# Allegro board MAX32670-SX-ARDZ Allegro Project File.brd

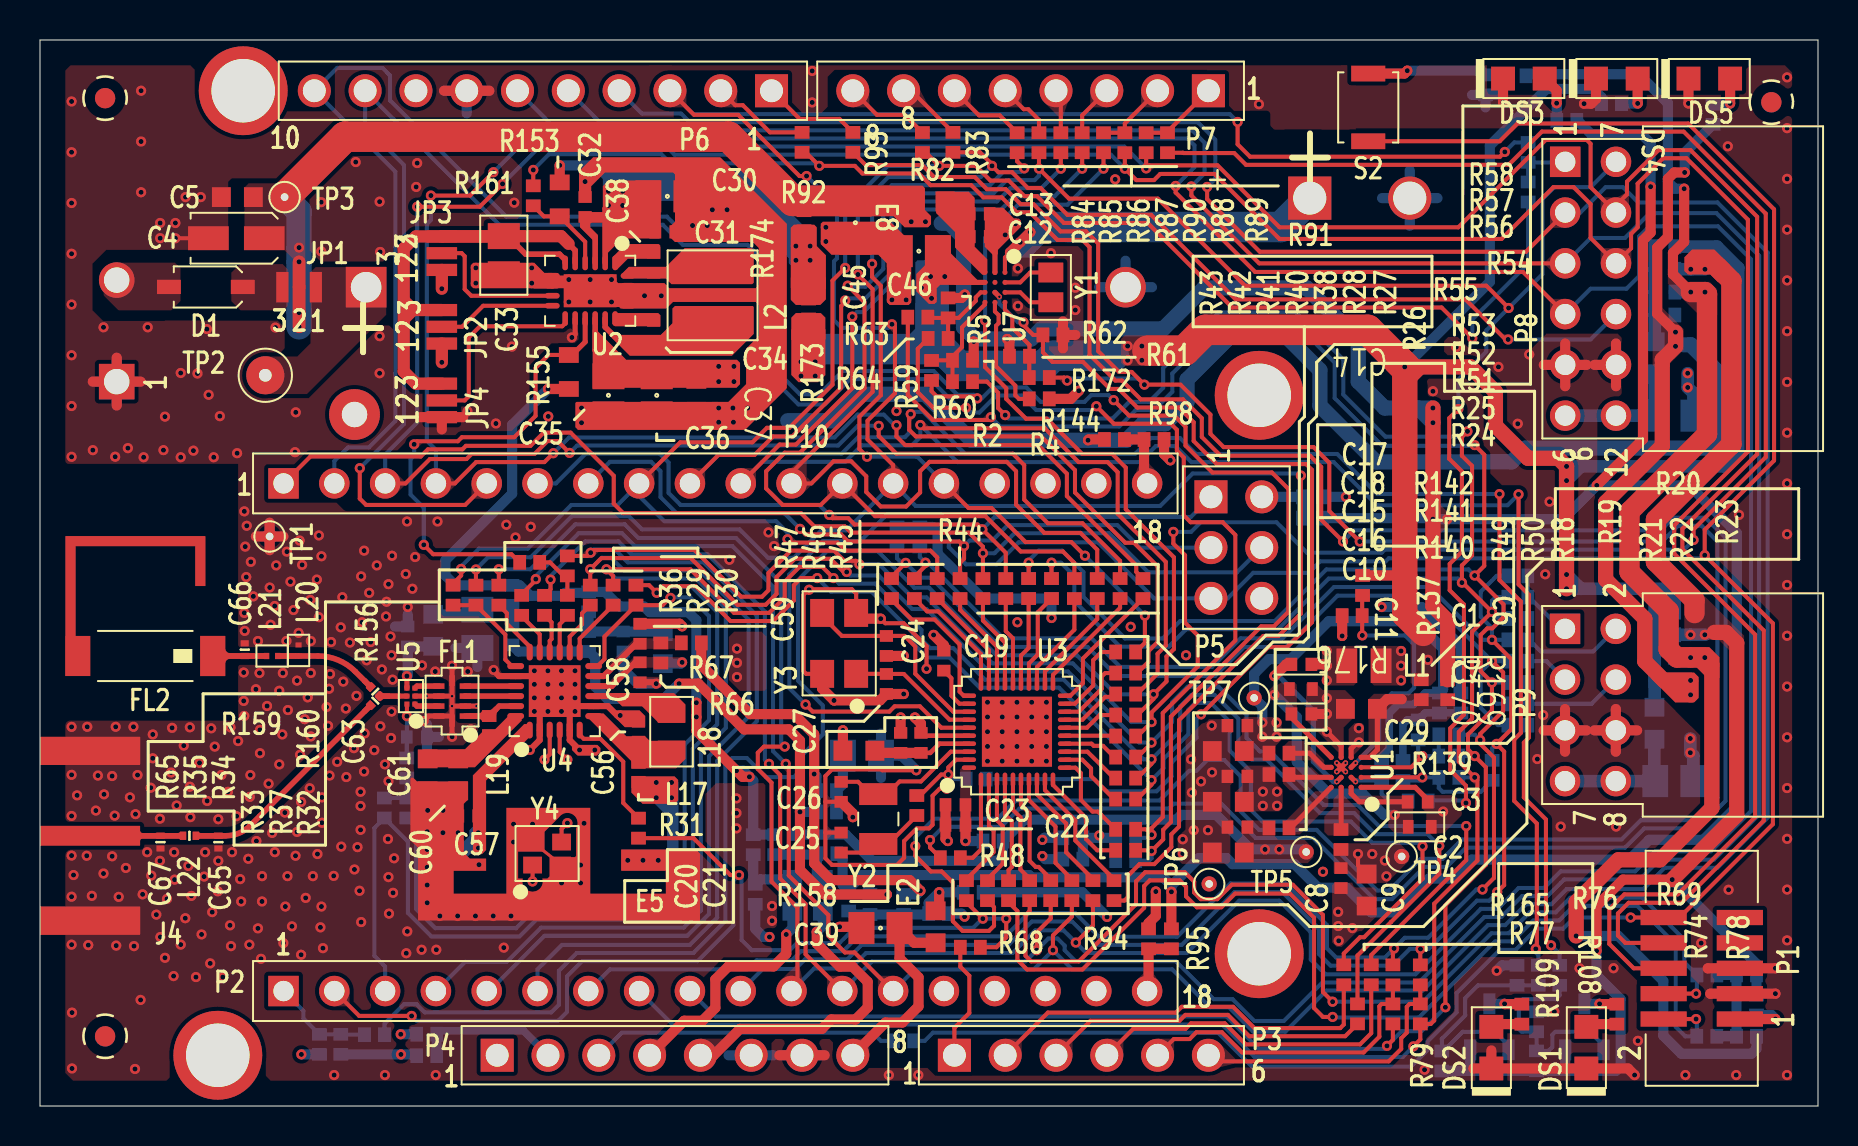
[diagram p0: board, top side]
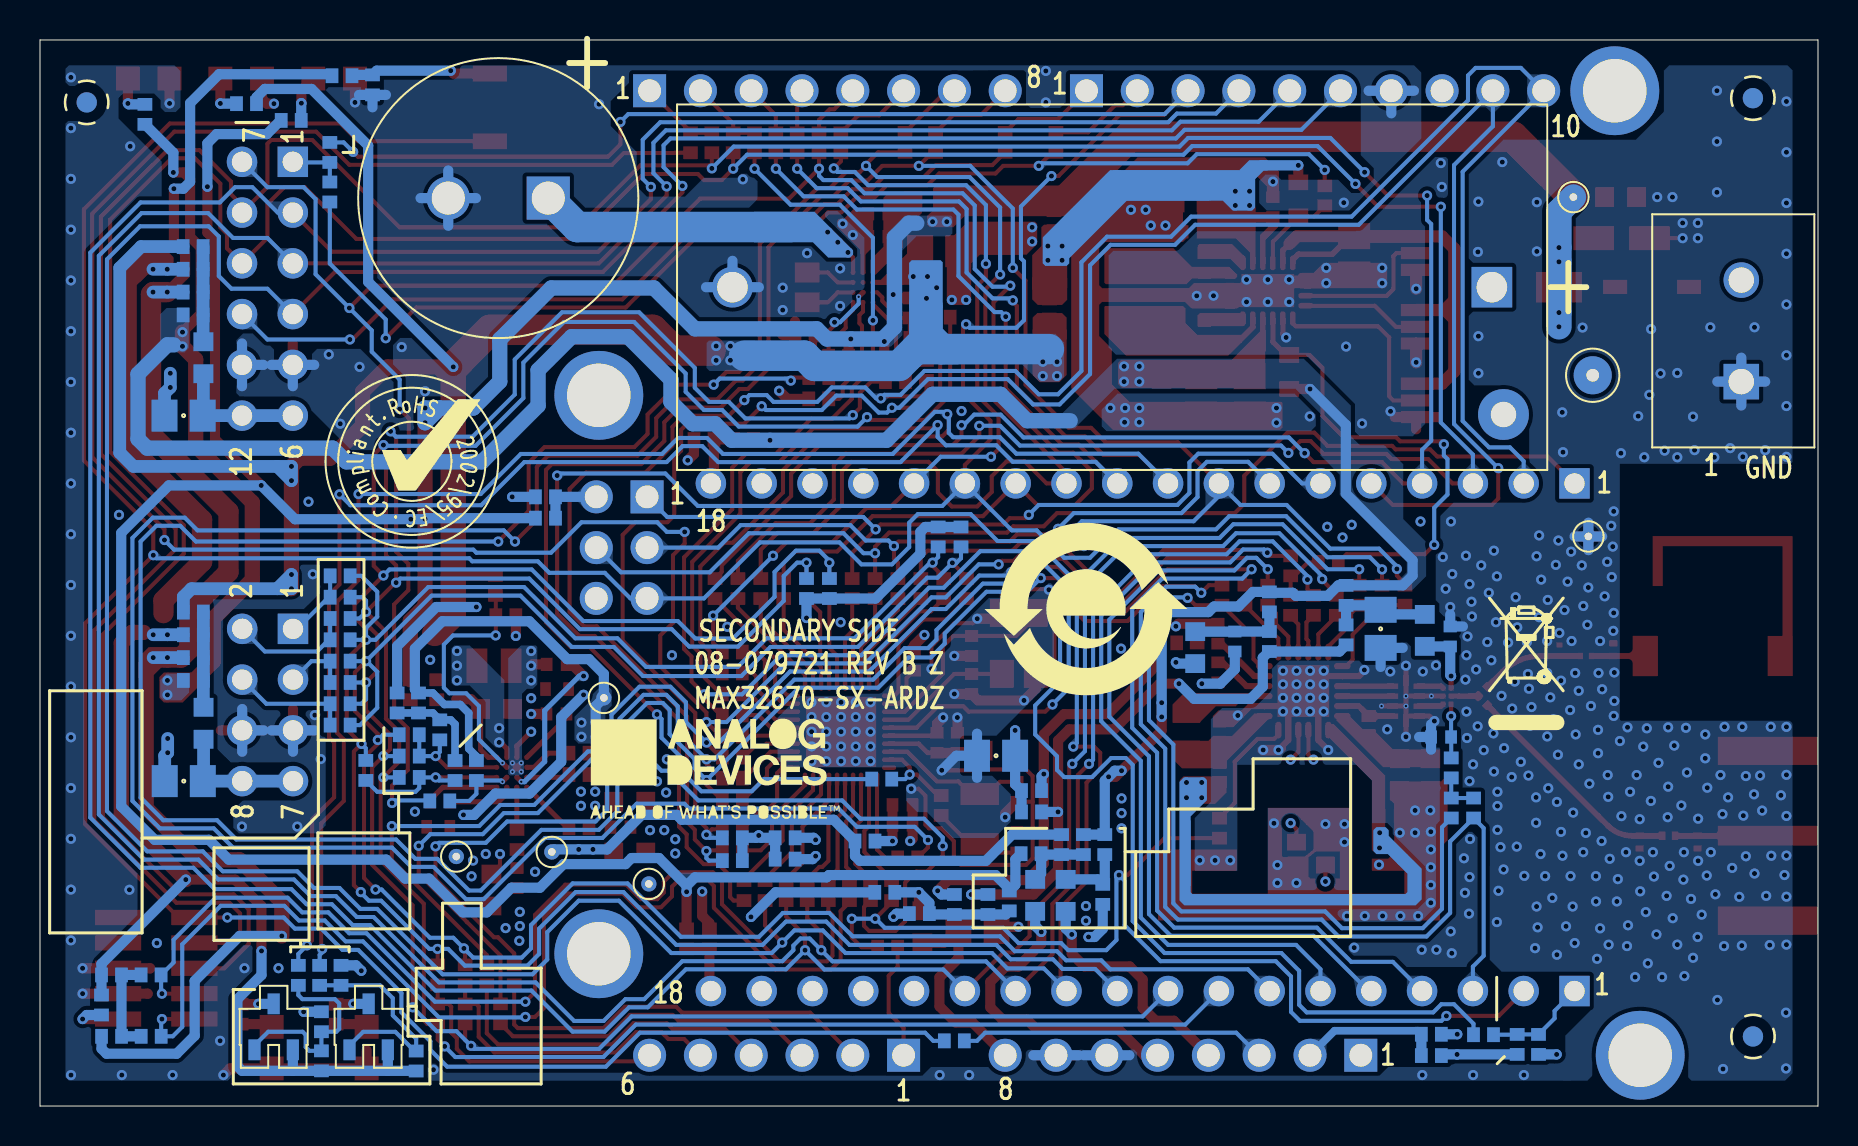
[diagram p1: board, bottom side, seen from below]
Outline 88.9 x 53.34 mm; copper layers: TOP, L2_GND, L3_PWR, BOTTOM. Coordinates in mm from the lower left corner of the outline.
Outline path: 0,53.34 88.9,53.34 88.9,0 0,0 0,53.34

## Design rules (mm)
constraint set DEFAULT: min track width 0.203
net group 50OHM-CPWG: nets RFI_N_1261 RFI_P_1261 RFO_1261 UNNAMED_9_CAP_I41_N1 UNNAMED_9_CAP_I108_N1 UNNAMED_9_CAP_I108_N2 UNNAMED_9_CAP_I126_N1 UNNAMED_9_FLTRBP10P_I89_SWRFI UNNAMED_9_FLTRBP10P_I89_SWRFO UNNAMED_9_IND_I127_N2

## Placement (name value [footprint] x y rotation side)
BT1  BH123A  [SKTMPDBH123A]  16.31 40.97 0 bottom
C1  0.01uF  [C0402]  63.07 22.1 180 top
C2  10UF  [C0402H32]  68.99 13.97 180 top
C3  0.01uF  [C0402]  68.88 15.21 180 top
C4  10uF  [C3216]  9.82 43.42 180 top
C5  1uF  [C0603]  9.87 45.48 0 top
C6  10UF  [C0402H32]  63.05 20.86 0 top
C7  0.01uF  [C0402]  63.07 19.62 0 top
C8  0.01uF  [C0402]  65.05 11.4 270 top
C9  22uF  [C0603]  66.33 10.81 270 top
C10  0.01uF  [C0402]  59.87 13.95 180 top
C11  47UF  [C0603]  59.41 12.68 180 top
C12  0.1uF  [C0402]  46.99 43.5 0 top
C13  1UF  [C0402]  46.99 44.64 0 top
C14  0.33F  [CPLTH197D531H327]  63.49 45.43 0 bottom
C15  0.01uF  [C0402]  59.87 16.49 180 top
C16  47UF  [C0603]  59.41 15.22 180 top
C17  0.01uF  [C0402]  59.87 19.03 180 top
C18  22uF  [C0603]  59.41 17.76 180 top
C19  4.7NF  [C0402]  45.19 22.28 90 top
C20  1UF  [C0402]  43.03 18.17 270 top
C21  0.1uF  [C0402]  44.05 18.17 270 top
C22  1UF  [C0402]  45.77 14.06 180 top
C23  0.1uF  [C0402]  45.77 15.07 180 top
C24  12pF  [C0402]  42.32 23.02 270 top
C25  0.1uF  [C0402]  40.06 13.18 90 top
C26  0.1uF  [C0402]  40.06 15.72 270 top
C27  12pF  [C0402]  42.32 21.12 270 top
C28  1NF  [C0402]  18.39 23.49 270 bottom
C29  22uF  [C0603]  66.07 19.87 0 top
C30  10uF  [C0805H60]  31.37 45.52 180 top
C31  1UF  [C0402]  31.27 43.74 180 top
C32  1UF  [C0402]  27.25 44.98 270 top
C33  4.7uF  [C0805H53]  23.19 42.57 90 top
C34  0.1uF  [C0402]  30.68 38.79 270 top
C35  22UF  [C0805H60]  28.42 35.56 270 top
C36  22UF  [C0805H60]  30.84 35.56 270 top
C37  0.1uF  [C0603]  32.82 35.56 270 top
C38  0.1uF  [C0402]  30.68 42.19 270 top
C39  22UF  [C0805H60]  42.02 8.9 180 top
C40  22UF  [C0805H60]  81.72 34.54 0 bottom
C41  22UF  [C0805H60]  81.71 16.26 0 bottom
C42  22UF  [C0805H60]  41.1 17.53 0 bottom
C43  22UF  [C0402]  29.16 23.24 90 bottom
C44  22UF  [C0805H60]  21.87 23.88 270 bottom
C45  22UF  [C0805H60]  40.77 44.2 270 top
C46  22UF  [C0805H60]  43.94 42.77 180 top
C56  0.47UF  [C0402]  29.93 18.73 90 top
C57  10NF  [C0402]  21.42 14.51 0 top
C58  100NF  [C0402]  30 21.7 90 top
C59  100NF  [C0402]  30 23.63 90 top
C60  47NF  [C0603]  20.91 16.57 270 top
C61  47pF  [C0603]  19.38 16.57 270 top
C62  1NF  [C0402]  18.85 18.47 0 bottom
C63  39pF  [C0201]  16.77 20.29 45 top
C65  3.3pF  [C0201]  8.92 13.2 270 top
C66  2.4pF  [C0201]  10.24 22.83 90 top
C67  3.3pF  [C0201]  6.02 13.2 270 top
D1  1N5819HW-7-F  [SOD123-3]  8.29 40.98 180 top
DS1  SML-LXT0805YW-TR  [LXT0805]  77.32 2.92 90 top
DS2  SML-LXT0805YW-TR  [LXT0805]  72.57 2.92 90 top
DS3  SML-LXT0805YW-TR  [LXT0805]  74.19 51.41 0 top
DS4  SML-LXT0805YW-TR  [LXT0805]  78.84 51.41 0 top
DS5  SML-LXT0805YW-TR  [LXT0805]  83.46 51.41 0 top
E1  120OHM AT 100MEGHZ  [L0603]  37.62 10.54 90 bottom
E2  120OHM AT 100MEGHZ  [L0603]  44.78 8.97 90 top
E3  120OHM AT 100MEGHZ  [L0603]  80.72 19.15 90 bottom
E4  120OHM AT 100MEGHZ  [L0603]  80.73 37.44 90 bottom
E5  120OHM AT 100MEGHZ  [L0603]  40.94 17.78 0 top
E6  120OHM AT 100MEGHZ  [L0603]  31.14 22.94 270 bottom
E7  120OHM AT 100MEGHZ  [L0603]  19.66 23.8 270 bottom
E8  120OHM AT 100MEGHZ  [L0603]  44.45 45.26 0 top
E9  120OHM AT 100MEGHZ  [L0603]  39.14 10.54 90 bottom
FL1  862-928MEGHZ  [FLSML79W49H35]  20.6 20.26 90 top
FL2  915MEGHz  [FLSML276W79H35]  5.26 22.52 180 top
J4  32K145-400L5  [CNSMAL559W374H169]  2.36 13.52 180 top
JP1  3PIN_SOLDER_JUMPER  [JPRSLD03]  12.95 40.97 180 top
JP2  3PIN_SOLDER_JUMPER  [JPRSLD03]  20.09 38.99 90 top
JP3  3PIN_SOLDER_JUMPER  [JPRSLD03]  20.09 42.67 90 top
JP4  3PIN_SOLDER_JUMPER  [JPRSLD03]  20.09 35.31 90 top
L1  1.5UH  [L0806-2]  66.2 22.03 0 top
L2  10uH  [LSMSQ157H161]  33.63 40.56 90 top
L17  47nH  [L0402]  29.93 16.7 270 top
L18  15UH  [L0805H57]  31.58 18.73 90 top
L19  47nH  [L0402]  22.46 19.03 90 top
L20  12NH  [L0201H13]  12.93 22.79 270 top
L21  1NH  [L0201H13]  11.61 22.52 180 top
L22  0  [R0201]  7.47 13.52 180 top
NOREF  -  [unnamed]  3.26 50.43 0 top
NOREF#2  -  [#2]  44.88 75.51 0 top
NOREF#3  -  [#2]  -26.27 -60.11 0 top
NOREF#4  -  [unnamed]  10.16 50.8 0 top
NOREF#5  -  [#2]  -31.35 -65.19 0 top
NOREF#6  -  [#2]  -26.27 -60.11 0 top
NOREF#7  -  [#2]  -31.35 -65.19 0 top
NOREF#8  -  [#2]  88.9 0 90 top
NOREF#9  -  [#2]  134.79 111.23 0 top
NOREF#10  -  [#2]  -31.35 -65.19 0 top
NOREF#11  -  [unnamed]  8.89 2.54 90 top
NOREF#12  -  [unnamed]  60.96 35.56 270 top
NOREF#13  -  [unnamed]  60.96 7.62 180 top
NOREF#14  -  [#2]  210.96 263.61 0 top
NOREF#15  -  [#2]  -26.27 -60.11 0 top
NOREF#16  -  [unnamed]  86.57 50.22 0 top
NOREF#17  -  [#2]  0 53.34 0 top
NOREF#18  -  [unnamed]  3.26 3.49 0 top
NOREF#19  -  [unnamed]  3.26 50.43 180 bottom
NOREF#20  -  [unnamed]  86.56 50.22 180 bottom
NOREF#21  -  [#2]  70.31 32.26 180 bottom
NOREF#22  -  [#2]  14.78 18.87 180 bottom
NOREF#23  -  [#2]  55.45 16.84 180 bottom
NOREF#24  -  [#2]  36.6 24.87 180 bottom
NOREF#25  -  [unnamed]  3.25 3.48 180 bottom
P1  3220-10-0300-00  [CNSMMHDR2X5L443W201H228]  83.09 6.89 90 top
P2  FPH25448-S18S1014272640B  [CNTHMHDR1X18L1800W98H421]  12.18 5.75 0 top
P3  SSQ-106-03-G-S  [CNSAMTECSSQ-106-XX-X-S]  45.72 2.54 0 top
P4  SSQ-108-03-G-S  [CNSAMTECSSQ-108-XX-X-S]  22.86 2.54 0 top
P5  67996-406HLF  [CNTHMHDR2X3L300W190H338]  58.55 30.48 270 top
P6  SSQ-110-03-G-S  [CNSAMTECSSQ-110-XX-X-S]  36.58 50.8 180 top
P7  SSQ-108-03-G-S  [CNSAMTECSSQ-108-XX-X-S]  58.42 50.8 180 top
P8  PPPC062LJBN-RC  [CNHDRRA2X6H205]  76.26 47.24 270 top
P9  PPPC042LJBN-RC  [CNHDRRA2X4H206]  76.25 23.88 270 top
P10  FPH25448-S18S1014272640B  [CNTHMHDR1X18L1800W98H421]  12.18 31.15 0 top
P11  OSTTC022162  [CNHDR1X2H406]  3.84 36.25 90 bottom
Q1  PMV65XP,215  [SOT23_B]  77.22 3.96 180 bottom
Q2  PMV65XP,215  [SOT23_B]  72.47 3.96 180 bottom
R1  10K  [R0402]  54.28 12.28 0 bottom
R2  10K  [R0402]  46.13 37.31 180 top
R3  10K  [R0402]  54.28 13.42 0 bottom
R4  0  [R0402]  49.96 35.38 180 top
R5  10K  [R0402]  45.41 39.93 270 top
R6  0  [R0402]  51.64 12.35 0 bottom
R7  0  [R0402]  51.64 13.42 0 bottom
R8  10K  [R0402]  50.58 25.89 90 bottom
R9  10K  [R0402]  49.43 25.89 90 bottom
R10  0  [R0402]  63.63 30.48 180 bottom
R11  0  [R0402]  63.63 29.41 180 bottom
R12  0  [R0402]  41.5 10.08 90 bottom
R13  0  [R0402]  43.18 10.08 90 bottom
R14  10K  [R0402]  83.34 3.49 180 bottom
R15  10K  [R0402]  83.35 6.56 180 bottom
R16  10K  [R0402]  73.8 51.55 180 bottom
R17  0  [R0402]  72.28 51.09 270 bottom
R18  0  [R0402]  48.43 10.78 270 top
R19  0  [R0402]  49.48 10.78 270 top
R20  0  [R0402]  50.54 10.78 270 top
R21  0  [R0402]  51.59 10.78 270 top
R22  0  [R0402]  52.65 10.78 270 top
R23  0  [R0402]  53.7 10.78 270 top
R24  0  [R0402]  54.28 12.8 0 top
R25  0  [R0402]  54.28 13.85 0 top
R26  0  [R0402]  55.15 25.89 90 top
R27  0  [R0402]  54 25.89 90 top
R28  0  [R0402]  52.86 25.89 90 top
R29  0  [R0402]  28.66 25.56 270 top
R30  0  [R0402]  29.8 25.56 270 top
R31  0  [R0402]  29.93 13.9 90 top
R32  0  [R0402]  26.37 25.05 270 top
R33  0  [R0402]  24.08 25.05 270 top
R34  0  [R0402]  22.94 25.56 270 top
R35  0  [R0402]  21.8 25.56 270 top
R36  0  [R0402]  27.51 25.56 90 top
R37  0  [R0402]  25.23 25.05 90 top
R38  0  [R0402]  51.72 25.89 90 top
R39  100  [R0402]  18.34 16.92 90 bottom
R40  0  [R0402]  50.58 25.89 90 top
R41  0  [R0402]  49.43 25.89 90 top
R42  0  [R0402]  48.29 25.89 90 top
R43  0  [R0402]  47.15 25.89 90 top
R44  0  [R0402]  46 25.89 90 top
R45  0  [R0402]  44.86 25.89 90 top
R46  0  [R0402]  43.72 25.89 90 top
R47  0  [R0402]  42.57 25.89 90 top
R48  0  [R0402]  45.52 12.42 180 top
R49  0  [R0402]  46.32 10.78 270 top
R50  0  [R0402]  47.38 10.78 270 top
R51  0  [R0402]  54.28 15.36 0 top
R52  0  [R0402]  54.28 16.41 0 top
R53  0  [R0402]  54.28 17.46 0 top
R54  0  [R0402]  54.28 18.51 0 top
R55  0  [R0402]  54.28 19.56 0 top
R56  0  [R0402]  54.28 20.61 0 top
R57  0  [R0402]  54.28 21.67 0 top
R58  0  [R0402]  54.28 22.72 0 top
R59  0  [R0402]  44.58 36.8 90 top
R60  0  [R0402]  46.13 36.25 180 top
R61  10K  [R0402]  48.97 37.52 0 top
R62  0  [R0402]  50.65 38.58 0 top
R63  0  [R0402]  43.89 39.47 180 top
R64  0  [R0402]  44.91 38.4 180 top
R65  0  [R0402]  20.65 25.56 270 top
R66  0  [R0402]  31.04 22.67 90 top
R67  0  [R0402]  32.57 23.17 180 top
R68  0  [R0402]  46.52 7.95 0 top
R69  0  [R0402]  65.19 6.57 90 top
R70  0  [R0402]  81.24 41.87 0 bottom
R71  0  [R0402]  81.24 40.73 0 bottom
R72  0  [R0402]  81.23 23.58 0 bottom
R73  0  [R0402]  81.23 22.44 0 bottom
R74  0  [R0402]  65.87 4.61 90 top
R75  0  [R0402]  43.18 3.26 0 bottom
R76  0  [R0402]  69.02 6.56 90 top
R77  0  [R0402]  67.64 6.56 90 top
R78  0  [R0402]  67.64 4.61 270 top
R79  0  [R0402]  69.02 4.61 270 top
R80  0  [R0402]  19.33 2.52 180 bottom
R81  0  [R0402]  19.33 3.59 180 bottom
R82  0  [R0402]  44.12 48.21 90 top
R83  0  [R0402]  45.65 48.22 90 top
R84  0  [R0402]  48.86 48.2 90 top
R85  0  [R0402]  49.95 48.2 90 top
R86  0  [R0402]  51.04 48.2 90 top
R87  0  [R0402]  52.11 48.2 90 top
R88  0  [R0402]  54.24 48.2 90 top
R89  0  [R0402]  55.31 48.2 90 top
R90  0  [R0402]  53.17 48.2 90 top
R91  0  [R0402]  56.38 48.2 90 top
R92  0  [R0402]  38.1 48.22 90 top
R93  0  [R0402]  40.64 48.22 90 top
R94  0  [R0402]  55.43 8.37 90 top
R95  0  [R0402]  56.57 8.37 90 top
R96  0  [R0402]  74.41 45.73 90 bottom
R97  0  [R0402]  74.41 47.71 270 bottom
R98  0  [R0402]  55.7 33.35 0 top
R99  0  [R0402]  39.32 15.78 0 bottom
R100  0  [R0402]  39.32 14.72 0 bottom
R101  0  [R0402]  47.65 13.26 0 bottom
R102  0  [R0402]  75.98 6.54 270 bottom
R103  0  [R0402]  74.92 6.54 270 bottom
R104  1.1K  [R0402]  74.83 2.26 90 bottom
R105  150K  [R0402]  74.83 4.22 90 bottom
R106  1.1K  [R0402]  70.09 2.25 90 bottom
R107  150K  [R0402]  73.85 6.54 90 bottom
R108  470  [R0402]  78.84 4.6 270 top
R109  470  [R0402]  74.09 4.6 270 top
R110  0  [R0402]  73.89 26.53 0 bottom
R111  0  [R0402]  73.89 25.46 0 bottom
R112  0  [R0402]  73.89 21.19 0 bottom
R113  0  [R0402]  73.89 22.26 0 bottom
R114  0  [R0402]  73.89 23.33 180 bottom
R115  0  [R0402]  73.89 24.39 180 bottom
R116  0  [R0402]  73.89 20.13 180 bottom
R117  0  [R0402]  73.89 19.06 180 bottom
R118  10K  [R0402]  43.99 28.47 270 bottom
R119  10K  [R0402]  42.85 28.47 270 bottom
R120  10K  [R0402]  67.08 16.79 90 bottom
R121  4.7K  [R0402]  68.91 18.82 270 bottom
R122  4.7K  [R0402]  68.15 16.79 270 bottom
R123  0  [R0402]  70.44 18.58 0 bottom
R124  0  [R0402]  70.44 17.51 0 bottom
R125  0  [R0402]  70.44 16.44 0 bottom
R126  0  [R0402]  72.61 16.79 90 bottom
R127  0  [R0402]  44.93 9.63 0 bottom
R128  0  [R0402]  85.32 3.49 180 bottom
R129  0  [R0402]  85.33 6.56 180 bottom
R130  10K  [R0402]  13.97 3.08 90 bottom
R131  10K  [R0402]  15.04 3.08 90 bottom
R132  0  [R0402]  16.73 3.57 180 bottom
R133  0  [R0402]  81.24 39.58 0 bottom
R134  0  [R0402]  81.23 21.29 0 bottom
R135  0  [R0402]  17.22 14.91 90 bottom
R136  0  [R0402]  18.34 14.91 90 bottom
R137  0  [R0402]  66.13 26.05 270 top
R138  0  [R0402]  40.44 10.26 90 bottom
R139  0  [R0402]  65.05 13.34 270 top
R140  0  [R0402]  61.95 13.92 180 top
R141  0  [R0402]  61.95 16.59 180 top
R142  0  [R0402]  61.95 17.65 180 top
R143  0  [R0402]  35.66 13.08 90 bottom
R144  0  [R0402]  53.72 33.35 180 top
R145  0  [R0402]  27.43 25.22 270 bottom
R146  0  [R0402]  27.43 23.24 90 bottom
R147  0  [R0402]  23.6 25.55 270 bottom
R148  0  [R0402]  23.6 23.57 90 bottom
R149  0  [R0402]  71.04 20.17 270 bottom
R150  0  [R0402]  69.98 20.17 270 bottom
R151  470  [R0402]  76.34 49.31 180 bottom
R152  470  [R0402]  78.57 50.15 0 bottom
R153  2MEG  [R0603]  25.98 45.36 270 top
R154  470  [R0402]  83.65 49.62 90 bottom
R155  2MEG  [R0603]  26.44 36.73 270 top
R156  0  [R0201]  16.77 20.74 135 top
R157  0  [R0402]  46.81 16.36 0 bottom
R158  0  [R0402]  43.84 15.04 270 top
R159  0  [R0402]  24.49 27.2 0 top
R160  0  [R0402]  26.37 27.03 270 top
R161  0  [R0402]  24.66 45.54 270 top
R162  0  [R0402]  39.34 12.62 0 bottom
R163  0  [R0402]  37.82 13.08 90 bottom
R164  0  [R0402]  36.73 13.08 90 bottom
R165  0  [R0402]  66.56 6.57 90 top
R166  0  [R0402]  46.66 10.69 0 bottom
R167  0  [R0402]  81.23 24.71 0 bottom
R168  0  [R0402]  81.24 43 0 bottom
R169  0  [R0402]  70.38 20.83 270 top
R170  0  [R0402]  69.06 20.83 270 top
R171  0  [R0402]  68.91 15.27 0 bottom
R172  0  [R0402]  49.96 36.45 0 top
R173  0  [R0402]  38.43 39.88 90 top
R174  0  [R0402]  38.2 44.3 270 top
R175  0  [R0402]  85.83 5.05 270 bottom
R176  0  [R0402]  65.61 24.54 180 top
R177  0  [R0402]  35.76 10.59 270 bottom
S1  B3U-1000P  [SWSML118W98H69]  66.41 49.97 270 top
TP1  TESTPAD  [TPC30D15]  11.48 28.5 0 top
TP2  TESTPAD  [TPC75D25]  11.26 36.56 0 top
TP3  TESTPAD  [TPC30D15]  12.23 45.48 0 top
TP4  TESTPAD  [TPC30D15]  68.08 12.48 0 top
TP5  TESTPAD  [TPC30D15]  63.31 12.71 0 top
TP6  TESTPAD  [TPC30D15]  58.46 11.11 0 top
TP7  TESTPAD  [TPC30D15]  60.71 20.42 0 top
U1  MAX77675AEWE+  [WLCSP16H27_A]  65.31 16.7 90 top
U2  LTC3130EUDC-1#PBF  [QFN20_4X3_PAD2_65X1_65]  27.51 40.79 180 top
U3  MAX32670GTL+  [QFN40_5X5_PAD3_5X3_5]  48.85 18.73 0 top
U4  SX1261IMLTRT  [QFN24_4X4_PAD2_6X2_6]  25.73 20.76 0 top
U5  BGS12WN6E6327XTSA1  [TSNP-6-10]  18.55 20.51 90 top
U7  MAX31334EWC+  [WLP12_1_968X1_468H0_69]  47.75 40.96 270 top
Y1  32.768KHZ  [YSML81W47H24_A]  50.54 40.96 270 top
Y2  32.768KHZ  [YSML126W59H35]  41.91 14.36 90 top
Y3  32MHZ  [YSML160W98H32]  39.96 23.15 90 top
Y4  32MEGHZ  [YSML79W63H20]  25.35 12.63 0 top

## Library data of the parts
BT1 = SKTBAT2P: User Part Number: UPN; Tolerance: N/A; alternate symbols: (SKTMPDBH123A); part number: SKTBAT2P_TH-BH123A,E062744,SKTMPDBH123A; tolerance: N/A
C1 C3 C7 C8 C10 C15 C17 = CAP: User Part Number: UPN; Tolerance: 10; alternate symbols: (C0402); part number: CAP_SM-0.01UF,25V,10,E013688,C0402; tolerance: 10
C2 C6 = CAP: User Part Number: UPN; Tolerance: 20; alternate symbols: (C0402H32); part number: CAP_SM-10UF,10V,20,E057793,C0402H32; tolerance: 20
C4 = CAPP: Tolerance: 20; User Part Number: UPN; alternate symbols: (C3216); part number: CAPP_SM-10UF,20V,20,E018828,C3216; tolerance: 20
C5 = CAP: User Part Number: UPN; Tolerance: 10; alternate symbols: (C0603); part number: CAP_SM-1UF,16V,10,E020111,C0603; tolerance: 10
C9 C18 = CAP: User Part Number: UPN; Tolerance: 20; alternate symbols: (C0603); part number: CAP_SM-22UF,10V,20,E022680,C0603; tolerance: 20
C11 C16 = CAP: User Part Number: UPN; Tolerance: 20; alternate symbols: (C0603); part number: CAP_SM-47UF,6.3V,20,E061424,C0603; tolerance: 20
C12 C21 C23 C25 C26 C34 C38 = CAP: User Part Number: UPN; Tolerance: 10; alternate symbols: (C0402); part number: CAP_SM-0.1UF,50V,10,E025746,C0402; tolerance: 10
C13 C20 C22 C31 C32 = CAP: User Part Number: UPN; Tolerance: 10; alternate symbols: (C0402); part number: CAP_SM-1UF,25V,10,E054542,C0402; tolerance: 10
C14 = CAPP: User Part Number: UPN; Tolerance: -20%,+80; alternate symbols: (CPLTH197D531H327); part number: CAPP_TH-0.33F,5.5V,-20%,+80,E062377,CPLTH197D531H327; tolerance: -20%,+80
C19 = CAP: User Part Number: UPN; Tolerance: 10; alternate symbols: (C0402); part number: CAP_SM-4.7NF,16V,10,E042800,C0402; tolerance: 10
C24 C27 = CAP: User Part Number: UPN; Tolerance: 5; alternate symbols: (C0402); part number: CAP_SM-12PF,50V,5,E033360,C0402; tolerance: 5
C28 C62 = CAP: User Part Number: UPN; Tolerance: 10; alternate symbols: (C0402); part number: CAP_SM-1NF,25V,10,E042764,C0402; tolerance: 10
C29 = CAP: User Part Number: UPN; Tolerance: 20; alternate symbols: (C0603); part number: CAP_SM-22UF,10V,20,E035951,C0603; tolerance: 20
C30 = CAP: Tolerance: 10; User Part Number: UPN; alternate symbols: (C0805H60); part number: CAP_SM-10UF,25V,10,E026259,C0805H60; tolerance: 10
C33 = CAP: Tolerance: 10; User Part Number: UPN; alternate symbols: (C0805H53); part number: CAP_SM-4.7UF,50V,10,E028468,C0805H53; tolerance: 10
C35 C36 C39-C42 C44-C46 = CAP: Tolerance: 20; User Part Number: UPN; alternate symbols: (C0805H60); part number: CAP_SM-22UF,10V,20,E059803,C0805H60; tolerance: 20
C37 = CAP: User Part Number: UPN; Tolerance: 10; alternate symbols: (C0603); part number: CAP_SM-0.1UF,25V,10,E007204,C0603; tolerance: 10
C43 = CAP: User Part Number: UPN; Tolerance: 20; alternate symbols: (C0402); part number: CAP_SM-22UF,6.3V,20,E059974,C0402; tolerance: 20
C56 = CAP: User Part Number: UPN; Tolerance: 10; alternate symbols: (C0402); part number: CAP_SM-0.47UF,16V,10,E047983,C0402; tolerance: 10
C57 = CAP: User Part Number: UPN; Tolerance: 10; alternate symbols: (C0402); part number: CAP_SM-10NF,25V,10,E046235,C0402; tolerance: 10
C58 C59 = CAP: User Part Number: UPN; Tolerance: 10; alternate symbols: (C0402); part number: CAP_SM-100NF,25V,10,E060176,C0402; tolerance: 10
C60 = CAP: User Part Number: UPN; Tolerance: 10; alternate symbols: (C0603); part number: CAP_SM-47NF,100V,10,E044215,C0603; tolerance: 10
C61 = CAP: User Part Number: UPN; Tolerance: 5; alternate symbols: (C0603); part number: CAP_SM-47PF,100V,5,E007959,C0603; tolerance: 5
C63 = CAP: Tolerance: 5; User Part Number: UPN; alternate symbols: (C0201); part number: CAP_SM-39PF,25V,5,E026816,C0201; tolerance: 5
C65 C67 = CAP: Tolerance: 0.25pF; User Part Number: UPN; alternate symbols: (C0201); part number: CAP_SM-3.3PF,25V,0.25PF,E017482,C0201; tolerance: 0.25pF
C66 = CAP: Tolerance: 0.1pF; User Part Number: UPN; alternate symbols: (C0201); part number: CAP_SM-2.4PF,25V,0.1PF,E031690,C0201; tolerance: 0.1pF
D1 = DIOSCHOTTKY: Tolerance: N/A; User Part Number: UPN; alternate symbols: (SOD123-3); part number: DIOSCHOTTKY_SM-1N5819HW-7-F,40V,N/A,E014276,SOD123-3; tolerance: N/A
DS1-DS5 = DIOLED: Tolerance: N/A; User Part Number: UPN; alternate symbols: (LXT0805); part number: DIOLED_SM-SML-LXT0805YW-TR,N/A,N/A,E005351,LXT0805; tolerance: N/A
E1-E9 = FERRITE: User Part Number: UPN; Tolerance: 25; alternate symbols: (L0603); part number: FERRITE_SM-120OHM AT 100MEGHZ,25,E025768,L0603; tolerance: 25
FL1 = FLTRBP10P: User Part Number: UPN; Tolerance: N/A; alternate symbols: (FLSML79W49H35); part number: FLTRBP10P_SM-862-928MEGHZ,E062117,FLSML79W49H35; tolerance: N/A
FL2 = FLTRRF2P: Tolerance: N/A; User Part Number: UPN; alternate symbols: (FLSML276W79H35); part number: FLTRRF2P_SM-915MEGHZ,E014743,FLSML276W79H35; tolerance: N/A
J4 = CNBNC5P: Tolerance: N/A; User Part Number: UPN; alternate symbols: (CNSMAL559W374H169); part number: CNBNC5P_SM-32K145-400L5,E015227,CNSMAL559W374H169; tolerance: N/A
JP1-JP4 = NC3P_JMPR: Tolerance: N/A; User Part Number: UPN; alternate symbols: (JPRSLD03); part number: NC3P_JMPR_SM-3PIN_SOLDER_JUMPER,E005606,JPRSLD03; tolerance: N/A
L1 = IND: Tolerance: 20; User Part Number: UPN; alternate symbols: (L0806-2); part number: IND_SM-1.5UH,20,E062341,L0806-2; tolerance: 20
L2 = IND: User Part Number: UPN; Tolerance: 20; alternate symbols: (LSMSQ157H161); part number: IND_SM-10UH,20,E016513,LSMSQ157H161; tolerance: 20
L17 L19 = IND: User Part Number: UPN; Tolerance: 5; alternate symbols: (L0402); part number: IND_SM-47NH,5,E010282,L0402; tolerance: 5
L18 = IND: User Part Number: UPN; Tolerance: 20; alternate symbols: (L0805H57); part number: IND_SM-15UH,20,E062262,L0805H57; tolerance: 20
L20 = IND: Tolerance: 3; User Part Number: UPN; alternate symbols: (L0201H13); part number: IND_SM-12NH,3,E031685,L0201H13; tolerance: 3
L21 = IND: Tolerance: 0.1NH; User Part Number: UPN; alternate symbols: (L0201H13); part number: IND_SM-1NH,0.1NH,E025902,L0201H13; tolerance: 0.1NH
L22 R156 = RES: Tolerance: JUMPER; User Part Number: UPN; alternate symbols: (R0201); part number: RES_SM-0,E004015,1/20W,JUMPER,R0201; tolerance: JUMPER
P1 = CN10P: User Part Number: UPN; Tolerance: N/A; alternate symbols: (CNSMMHDR2X5L443W201H228); part number: CN10P_SM-3220-10-0300-00,E027502,CNSMMHDR2X5L443W201H228; tolerance: N/A
P2 P10 = CN18P: Tolerance: N/A; User Part Number: UPN; alternate symbols: (CNTHMHDR1X18L1800W98H421); part number: CN18P_TH-FPH25448-S18S1014272640B,E056935,CNTHMHDR1X18L1800W98H421; tolerance: N/A
P3 = CN6P: User Part Number: UPN; Tolerance: N/A; alternate symbols: (CNSAMTECSSQ-106-XX-X-S); part number: CN6P_TH-SSQ-106-03-G-S,E020477,CNSAMTECSSQ-106-XX-X-S; tolerance: N/A
P4 P7 = CN8P_A: User Part Number: UPN; Tolerance: N/A; alternate symbols: (CNSAMTECSSQ-108-XX-X-S); part number: CN8P_A_TH-SSQ-108-03-G-S,E020478,CNSAMTECSSQ-108-XX-X-S; tolerance: N/A
P5 = CN6P: User Part Number: UPN; Tolerance: N/A; alternate symbols: (CNTHMHDR2X3L300W190H338); part number: CN6P_TH-67996-406HLF,E027385,CNTHMHDR2X3L300W190H338; tolerance: N/A
P6 = CN10P: User Part Number: UPN; Tolerance: N/A; alternate symbols: (CNSAMTECSSQ-110-XX-X-S); part number: CN10P_TH-SSQ-110-03-G-S,E020479,CNSAMTECSSQ-110-XX-X-S; tolerance: N/A
P8 = CN12P_V3: User Part Number: UPN; Tolerance: N/A; alternate symbols: (CNHDRRA2X6H205); part number: CN12P_V3_TH-PPPC062LJBN-RC,E022332,CNHDRRA2X6H205; tolerance: N/A
P9 = CN8P_ODD_EVEN: User Part Number: UPN; Tolerance: N/A; alternate symbols: (CNHDRRA2X4H206); part number: CN8P_ODD_EVEN_TH-PPPC042LJBN-RC,E023816,CNHDRRA2X4H206; tolerance: N/A
P11 = CN2P: User Part Number: UPN; Tolerance: N/A; alternate symbols: (CNHDR1X2H406); part number: CN2P_TH-OSTTC022162,E016936,CNHDR1X2H406; tolerance: N/A
Q1 Q2 = TRANPMOSFET_V12: User Part Number: UPN; Tolerance: N/A; alternate symbols: (SOT23_B); part number: TRANPMOSFET_V12_SM-PMV65XP,215,E027303,SOT23_B; tolerance: N/A
R1-R3 R5 R8 R9 R14-R16 R61 R118-R120 R130 R131 = RES: User Part Number: UPN; Tolerance: 1; alternate symbols: (R0402); part number: RES_SM-10K,E003751,1/10W,1,R0402; tolerance: 1
R4 R6 R7 R10-R13 R17-R38 R40-R60 R62-R103 R110-R117 R123-R129 R132-R150 R157-R177 = RES: User Part Number: UPN; Tolerance: JUMPER; alternate symbols: (R0402); part number: RES_SM-0,E003438,1/10W,JUMPER,R0402; tolerance: JUMPER
R39 = RES: User Part Number: UPN; Tolerance: 5; alternate symbols: (R0402); part number: RES_SM-100,E003443,1/10W,5,R0402; tolerance: 5
R104 R106 = RES: User Part Number: UPN; Tolerance: 1; alternate symbols: (R0402); part number: RES_SM-1.1K,E026460,1/16W,1,R0402; tolerance: 1
R105 R107 = RES: User Part Number: UPN; Tolerance: 1; alternate symbols: (R0402); part number: RES_SM-150K,E020496,1/10W,1,R0402; tolerance: 1
R108 R109 R151 R152 R154 = RES: User Part Number: UPN; Tolerance: 1; alternate symbols: (R0402); part number: RES_SM-470,E014032,1/16W,1,R0402; tolerance: 1
R121 R122 = RES: User Part Number: UPN; Tolerance: 1; alternate symbols: (R0402); part number: RES_SM-4.7K,E008190,1/10W,1,R0402; tolerance: 1
R153 R155 = RES: User Part Number: UPN; Tolerance: 1; alternate symbols: (R0603); part number: RES_SM-2MEG,E021609,1/10W,1,R0603; tolerance: 1
S1 = SWSPST2PIN_V2: Tolerance: N/A; User Part Number: UPN; alternate symbols: (SWSML118W98H69); part number: SWSPST2PIN_V2_SM-B3U-1000P,E016303,SWSML118W98H69; tolerance: N/A
TP1 TP3-TP7 = NCTESTPAD: Tolerance: N/A; User Part Number: UPN; alternate symbols: (TPC30D15); part number: NCTESTPAD_TH-TESTPAD,E013464,TPC30D15; tolerance: N/A
TP2 = NCTESTPAD: Tolerance: N/A; User Part Number: UPN; alternate symbols: (TPC75D25); part number: NCTESTPAD_TH-TESTPAD,E020792,TPC75D25; tolerance: N/A
U1 = ADMAX77675: Tolerance: N/A; User Part Number: UPN; alternate symbols: (WLCSP16H27_A); part number: ADMAX77675_SM-MAX77675AEWE+,E062342,WLCSP16H27_A; tolerance: N/A
U2 = ADLTC3130_V2: User Part Number: UPN; Tolerance: N/A; alternate symbols: (QFN20_4X3_PAD2_65X1_65); part number: ADLTC3130_V2_SM-LTC3130EUDC-1#PBF,E054840,QFN20_4X3_PAD2_65X1_65; tolerance: N/A
U3 = ICMAX3267X: User Part Number: UPN; Tolerance: N/A; alternate symbols: (QFN40_5X5_PAD3_5X3_5); part number: ICMAX3267X_SM-MAX32670GTL+,E047559,QFN40_5X5_PAD3_5X3_5; tolerance: N/A
U4 = ICSX126X: Tolerance: N/A; User Part Number: UPN; alternate symbols: (QFN24_4X4_PAD2_6X2_6); part number: ICSX126X_SM-SX1261IMLTRT,E061830,QFN24_4X4_PAD2_6X2_6; tolerance: N/A
U5 = ICBGS12WN6: User Part Number: UPN; Tolerance: N/A; alternate symbols: (TSNP-6-10); part number: ICBGS12WN6_SM-BGS12WN6E6327XTSA1,E062135,TSNP-6-10; tolerance: N/A
U7 = ADMAX31334: User Part Number: UPN; Tolerance: N/A; alternate symbols: (WLP12_1_968X1_468H0_69); part number: ADMAX31334_SM-MAX31334EWC+,E062116,WLP12_1_968X1_468H0_69; tolerance: N/A
Y1 = XTAL: Tolerance: N/A; alternate symbols: (YSML81W47H24_A); part number: XTAL_SM-32.768KHZ,E062379,YSML81W47H24_A; tolerance: N/A
Y2 = XTAL: User Part Number: UPN; Tolerance: N/A; alternate symbols: (YSML126W59H35); part number: XTAL_SM-32.768KHZ,E062517,YSML126W59H35; tolerance: N/A
Y3 = XTAL4PIN_V5: User Part Number: UPN; Tolerance: N/A; alternate symbols: (YSML160W98H32); part number: XTAL4PIN_V5_SM-32MHZ,E062554,YSML160W98H32; tolerance: N/A
Y4 = XTAL4PIN_V9: Tolerance: 10PPM; User Part Number: UPN; alternate symbols: (YSML79W63H20); part number: XTAL4PIN_V9_SM-32MEGHZ,E062134,YSML79W63H20; tolerance: 10PPM

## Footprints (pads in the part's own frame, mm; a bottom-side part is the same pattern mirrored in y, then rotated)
C0201
  rect 0.305x0.406 smd: 1(-0.318,0) 2(0.318,0)
C0402
  rect 0.584x0.66 smd: 1(-0.5,0) 2(0.5,0)
C0402H32
  rect 0.533x0.686 smd: 1(-0.577,0) 2(0.577,0)
C0603
  rect 0.94x0.991 smd: 1(-0.8,0) 2(0.8,0)
C0805H53
  rect 1.295x1.6 smd: 1(-0.953,0) 2(0.953,0)
C0805H60
  rect 1.295x1.6 smd: 1(-0.953,0) 2(0.953,0)
C3216
  rect 2.032x1.194 smd: N(1.397,0) P(-1.397,0)
CNHDR1X2H406
  rect 1.778x1.778 hole 1.27: 1(0,0)
  round 1.778 hole 1.27: 2(5.08,0)
CNHDRRA2X4H206
  rect 1.524x1.524 hole 1.016: 1(0,0)
  round 1.524 hole 1.016: 2(0,2.54) 3(2.54,0) 4(2.54,2.54) 5(5.08,0) 6(5.08,2.54) 7(7.62,0) 8(7.62,2.54)
CNHDRRA2X6H205
  rect 1.524x1.524 hole 1.016: 1(0,0)
  round 1.524 hole 1.016: 2(2.54,0) 3(5.08,0) 4(7.62,0) 5(10.16,0) 6(12.7,0) 7(0,2.54) 8(2.54,2.54) 9(5.08,2.54) 10(7.62,2.54) 11(10.16,2.54) 12(12.7,2.54)
CNSAMTECSSQ-106-XX-X-S
  rect 1.651x1.651 hole 1.143: 1(0,0)
  round 1.651 hole 1.143: 2(2.54,0) 3(5.08,0) 4(7.62,0) 5(10.16,0) 6(12.7,0)
CNSAMTECSSQ-108-XX-X-S
  rect 1.651x1.651 hole 1.143: 1(0,0)
  round 1.651 hole 1.143: 2(2.54,0) 3(5.08,0) 4(7.62,0) 5(10.16,0) 6(12.7,0) 7(15.24,0) 8(17.78,0)
CNSAMTECSSQ-110-XX-X-S
  rect 1.651x1.651 hole 1.143: 1(0,0)
  round 1.651 hole 1.143: 2(2.54,0) 3(5.08,0) 4(7.62,0) 5(10.16,0) 6(12.7,0) 7(15.24,0) 8(17.78,0) 9(20.32,0) 10(22.86,0)
CNSMAL559W374H169
  rect 5.004x0.991 smd: 1(-0.14,0)
  rect 5.004x1.397 smd: 2(-0.14,4.248) 3(-0.14,4.248) 4(-0.14,-4.248) 5(-0.14,-4.248)
CNSMMHDR2X5L443W201H228
  rect 0.762x2.311 smd: 1(-2.54,-1.906) 2(-2.54,1.906) 3(-1.27,-1.906) 4(-1.27,1.906) 5(0,-1.906) 6(0,1.906) 7(1.27,-1.906) 8(1.27,1.906) 9(2.54,-1.906) 10(2.54,1.906)
CNTHMHDR1X18L1800W98H421
  rect 1.524x1.524 hole 1.016: 1(0,0)
  round 1.524 hole 1.016: 2(2.54,0) 3(5.08,0) 4(7.62,0) 5(10.16,0) 6(12.7,0) 7(15.24,0) 8(17.78,0) 9(20.32,0) 10(22.86,0) 11(25.4,0) 12(27.94,0) 13(30.48,0) 14(33.02,0) 15(35.56,0) 16(38.1,0) 17(40.64,0) 18(43.18,0)
CNTHMHDR2X3L300W190H338
  rect 1.651x1.651 hole 1.143: 1(0,0)
  round 1.651 hole 1.143: 2(0,2.54) 3(2.54,0) 4(2.54,2.54) 5(5.08,0) 6(5.08,2.54)
CPLTH197D531H327
  round 2.159 hole 1.651: N(5,0)
  rect 2.159x2.159 hole 1.651: P(0,0)
FLSML79W49H35
  rect 0.279x0.559 smd: 1(-0.75,-0.66) 2(-0.25,-0.66) 3(0.25,-0.66) 4(0.75,-0.66) 6(0.75,0.66) 7(0.25,0.66) 8(-0.25,0.66) 9(-0.75,0.66)
  rect 0.533x0.279 smd: 5(1.023,0) 10(-1.023,0)
FLSML276W79H35
  rect 1.245x2.007 smd: 1(-3.372,0) 2(3.372,0)
JPRSLD03
  rect 0.61x1.524 smd: 1(-0.838,0) 2(0,0) 3(0.838,0)
L0201H13
  rect 0.254x0.305 smd: 1(-0.277,0) 2(0.277,0)
L0402
  rect 0.584x0.711 smd: 1(-0.475,0) 2(0.475,0)
L0603
  rect 0.94x0.991 smd: 1(-0.8,0) 2(0.8,0)
L0805H57
  rect 0.914x1.372 smd: 1(-0.902,0) 2(0.902,0)
L0806-2
  rect 1.041x1.727 smd: 1(-0.856,0) 2(0.856,0)
LSMSQ157H161
  rect 0.965x3.708 smd: 1(-1.181,0) 2(1.181,0)
LXT0805
  rect 1.194x1.194 smd: A(1.041,0) C(-1.041,0)
QFN20_4X3_PAD2_65X1_65
  oval 0.279x0.737 smd: 1(-1.25,-1.393) 2(-0.75,-1.393) 3(-0.25,-1.393) 4(0.25,-1.393) 5(0.75,-1.393) 6(1.25,-1.393) 11(1.25,1.393) 12(0.75,1.393) 13(0.25,1.393) 14(-0.25,1.393) 15(-0.75,1.393) 16(-1.25,1.393)
  oval 0.737x0.279 smd: 7(1.893,-0.75) 8(1.893,-0.25) 9(1.893,0.25) 10(1.893,0.75) 17(-1.893,0.75) 18(-1.893,0.25) 19(-1.893,-0.25) 20(-1.893,-0.75)
  rect 2.642x1.651 smd: PAD(0,0)
QFN24_4X4_PAD2_6X2_6
  oval 0.305x0.838 smd: 1(-1.25,-1.95) 2(-0.75,-1.95) 3(-0.25,-1.95) 4(0.25,-1.95) 5(0.75,-1.95) 6(1.25,-1.95) 13(1.25,1.95) 14(0.75,1.95) 15(0.25,1.95) 16(-0.25,1.95) 17(-0.75,1.95) 18(-1.25,1.95)
  oval 0.838x0.305 smd: 7(1.95,-1.25) 8(1.95,-0.75) 9(1.95,-0.25) 10(1.95,0.25) 11(1.95,0.75) 12(1.95,1.25) 19(-1.95,1.25) 20(-1.95,0.75) 21(-1.95,0.25) 22(-1.95,-0.25) 23(-1.95,-0.75) 24(-1.95,-1.25)
  rect 2.591x2.591 smd: PAD(0,0)
QFN40_5X5_PAD3_5X3_5
  oval 0.229x0.711 smd: 1(-1.8,-2.401) 2(-1.4,-2.401) 3(-1,-2.401) 4(-0.6,-2.401) 5(-0.2,-2.401) 6(0.2,-2.401) 7(0.6,-2.401) 8(1,-2.401) 9(1.4,-2.401) 10(1.8,-2.401) 21(1.8,2.401) 22(1.4,2.401) 23(1,2.401) 24(0.6,2.401) 25(0.2,2.401) 26(-0.2,2.401) 27(-0.6,2.401) 28(-1,2.401) 29(-1.4,2.401) 30(-1.8,2.401)
  oval 0.711x0.229 smd: 11(2.401,-1.8) 12(2.401,-1.4) 13(2.401,-1) 14(2.401,-0.6) 15(2.401,-0.2) 16(2.401,0.2) 17(2.401,0.6) 18(2.401,1) 19(2.401,1.4) 20(2.401,1.8) 31(-2.401,1.8) 32(-2.401,1.4) 33(-2.401,1) 34(-2.401,0.6) 35(-2.401,0.2) 36(-2.401,-0.2) 37(-2.401,-0.6) 38(-2.401,-1) 39(-2.401,-1.4) 40(-2.401,-1.8)
  rect 3.505x3.505 smd: PAD(0,0)
R0201
  rect 0.305x0.406 smd: 1(-0.318,0) 2(0.318,0)
R0402
  rect 0.635x0.737 smd: 1(-0.5,0) 2(0.5,0)
R0603
  rect 0.787x0.991 smd: 1(-0.85,0) 2(0.85,0)
SKTMPDBH123A
  round 2.54 hole 1.27 unplated: (-0.58,6.37)
  rect 2.032x2.032 hole 1.524: 1(0,0)
  round 2.032 hole 1.524: 2(37.97,0)
SOD123-3
  rect 1.194x0.711 smd: A(1.847,0) C(-1.847,0)
SOT23_B
  rect 0.61x1.041 smd: 1(-0.958,-1.15) 2(0.958,-1.15) 3(0,1.15)
SWSML118W98H69
  rect 0.787x1.702 smd: 1(-1.694,0) 2(1.694,0)
TPC30D15
  round 0.762 hole 0.381: 1(0,0)
TPC75D25
  round 1.905 hole 0.635: 1(0,0)
TSNP-6-10
  rect 0.254x0.254 smd: 1(-0.4,-0.2) 2(0,-0.2) 3(0.4,-0.2) 4(0.4,0.2) 5(0,0.2) 6(-0.4,0.2)
unnamed
  round 1.016 smd: (0,0)
WLCSP16H27_A
  round 0.254 smd: A1(-0.75,-0.75) A2(-0.75,-0.25) A3(-0.75,0.25) A4(-0.75,0.75) B1(-0.25,-0.75) B2(-0.25,-0.25) B3(-0.25,0.25) B4(-0.25,0.75) C1(0.25,-0.75) C2(0.25,-0.25) C3(0.25,0.25) C4(0.25,0.75) D1(0.75,-0.75) D2(0.75,-0.25) D3(0.75,0.25) D4(0.75,0.75)
WLP12_1_968X1_468H0_69
  round 0.254 smd: A1(-0.75,0.5) A2(-0.25,0.5) A3(0.25,0.5) A4(0.75,0.5) B1(-0.75,0) B2(-0.25,0) B3(0.25,0) B4(0.75,0) C1(-0.75,-0.5) C2(-0.25,-0.5) C3(0.25,-0.5) C4(0.75,-0.5)
YSML79W63H20
  rect 0.94x0.838 smd: 1(-0.725,-0.575) 2(0.725,-0.575) 3(0.725,0.575) 4(-0.725,0.575)
YSML81W47H24_A
  rect 0.991x1.245 smd: 1(-0.745,0) 2(0.745,0)
YSML126W59H35
  rect 1.092x1.905 smd: 1(-1.246,0) 2(1.246,0)
YSML160W98H32
  rect 1.397x1.194 smd: 1(-1.524,-0.851) 2(1.524,-0.851) 3(1.524,0.851) 4(-1.524,0.851)

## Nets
0V7_SSB2: C15.1 C16.1 R127.2(N2) R141.2(N2) R177.2(N2) TP6.1(N1)
1V1_SSB1: C10.1 C11.1 R101.2(N2) R140.2(N2) R163.2(N2) TP5.1(N1)
1V8_SSB0: C8.1 C9.1 R6.1 R13.2(N2) R16.1 R67.1 R71.2(N2) R73.2(N2) R80.2(N2) R99.1 R128.1 R131.1 R139.2(N2) R149.1 TP4.1(N1)
3V3_SSB3: C17.1 C18.1 Q1.2(S) Q2.2(S) R7.1 R10.1 R12.2(N2) R70.2(N2) R72.2(N2) R81.2(N2) R94.2(N2) R98.2(N2) R100.1 R104.1 R106.1 R120.2(N2) R129.1 R130.1 R142.2(N2) R146.1 R148.1 R150.1 R175.1 TP7.1(N1)
GND: BT1.2(N2) C2.1 C3.1 C4.N(N2) C5.1 C6.2(N2) C7.2(N2) C8.2(N2) C9.2(N2) C10.2(N2) C11.2(N2) C12.2(N2) C13.2(N2) C14.N(N2) C15.2(N2) C16.2(N2) C17.2(N2) C18.2(N2) C19.2(N2) C20.1 C21.1 C22.2(N2) C23.2(N2) C24.2(N2) C25.2(N2) C26.2(N2) C27.2(N2) C28.1 C29.1 C30.1 C31.1 C32.1 C33.1 C35.2(N2) C36.2(N2) C37.2(N2) C39.2(N2) C40.2(N2) C41.2(N2) C42.2(N2) C43.1 C44.2(N2) C45.2(N2) C46.2(N2) C56.2(N2) C57.1 C58.1 C59.2(N2) C60.2(N2) C61.2(N2) C62.2(N2) C65.2(N2) C66.2(N2) C67.2(N2) DS1.C DS2.C DS3.C DS4.C DS5.C FL1.2 FL1.5 FL1.7 FL1.9 FL1.10 J4.2 J4.3 J4.4 J4.5(SH4) JP2.1 JP3.1 JP4.1 L20.1 P1.3 P1.5 P2.17 P4.6 P4.7 P5.6(N6) P6.7 P8.5 P8.11 P9.5 P9.6 P11.1 R4.1 R17.2(N2) R62.2(N2) R105.2(N2) R107.2(N2) R176.2(N2) TP1.1(N1) U1.A1 U1.D3 U2.7 U2.8 U2.12 U2.17 U2.18 U2.19 U2.PAD U3.36(VSS) U3.PAD U4.2 U4.5 U4.8 U4.20 U4.PAD U5.2 U7.B1 Y3.2 Y3.4 Y4.2 Y4.4
VCC_3130: C33.2(N2) JP2.3 JP3.3 JP4.3 U2.5 U2.6
VCC_31334: C4.P C5.2(N2) C45.1 E8.1 JP1.2(COM) R2.1 R5.1 R11.1 R61.1 R95.2(N2) R138.2(N2) R151.1 R162.2(N2) R169.1 R174.1 TP3.1(N1)
VDD_IN_1261: C57.2(N2) L17.2(N2) U4.1
32K_OUT_32670: C26.1 U3.38 Y2.2(N2)
32KIN_32670: R157.1 R158.1 U3.39
CLKOUT_31334: R62.1 R157.2(N2) U7.B3
DCC_SW_1261: L18.2(N2) U4.9
DIO2_SX: R30.2(N2) R136.1 U4.12
HFXIN_32670: C24.1 U3.33 Y3.3(IN/OUT2)
HFXOUT_32670: C27.1 U3.34 Y3.1
I2C0_SCL_32670: P6.10 P10.2 R1.2(N2) R24.2(N2) R59.1
I2C0_SDA_32670: P6.9(N9) P10.5 R3.2(N2) R25.2(N2) R64.2(N2)
I2C1_SCL_32670: P2.8 R8.2(N2) R40.2(N2) R60.1 R79.2(N2) R111.1 R115.2(N2) R125.2(N2)
I2C1_SDA_32670: P2.9(N9) R9.2(N2) R41.2(N2) R63.2(N2) R78.2(N2) R112.1 R116.2(N2) R124.2(N2)
I2C2_SCL_32670: P2.10 R46.2(N2) R76.2(N2) R110.1 R114.2(N2) R118.2(N2) R126.2(N2)
I2C2_SDA_32670: P2.7 R47.2(N2) R77.2(N2) R113.1 R117.2(N2) R119.2(N2) R123.2(N2)
MODE: JP4.2(COM) U2.11
NRESET_1261: R32.1 R159.2(N2) R160.2(N2)
P0_21_32670: P2.2 R31.1 R49.2(N2) R68.2(N2)
P0_23_32670: P2.3 R30.1 R51.2(N2) R69.2(N2) R135.1
P0_24_32670: P2.4 R29.1 R52.2(N2) R74.2(N2)
P0_25_32670: P2.5 R36.2(N2) R53.2(N2) R165.2(N2)
P0_26_32670: P2.6 R54.2(N2) R91.1 R160.1
P0_27_32670: R55.2(N2) R90.1 R132.1
PGOOD_3130: R155.1 R159.1 U2.13
PSW_31334: C46.1 R137.1 R152.1 R166.2(N2) R167.2(N2) R168.2(N2) R170.1 R173.1 U7.C2
RFI_N_1261: FL1.3 U4.22
RFI_P_1261: FL1.4 U4.21
RFO_1261: FL1.1 L19.2(N2) U4.23
RSTN_32670: P1.10 P5.5 R75.2(N2) S1.2(B) U3.35
RUN_3130: R153.2(N2) R161.2(N2) U2.4
SPI0_MISO_32670: P2.12 P6.5 P8.3 R20.2(N2) R37.2(N2)
SPI0_MOSI_32670: P2.13 P6.4 P8.2 R21.2(N2) R33.1
SPI0_SCK_32670: P2.11 P6.6 P8.4 R22.2(N2) R34.1
SPI0_SS0_32670: P6.3 P10.13 R23.2(N2) R35.1 R97.1
SPI1_MISO_32670: P5.1 P10.6 R42.2(N2)
SPI1_MOSI_32670: P5.4 P10.1 R43.2(N2)
SPI1_SCK_32670: P5.3 P10.7 R44.2(N2)
SPI1_SS0_32670: P10.8 R45.2(N2) R65.1 R82.1 R96.1
SWDCLK_32670: P1.4 R15.2(N2) R19.2(N2)
SWDCLKB_32670: R48.2(N2) R92.1 R161.1
SWDIO_32670: P1.2 R14.2(N2) R18.2(N2)
SWDIOB_32670: R50.2(N2) R93.1 R172.2(N2)
UART0A_CTS_32670: P8.10 P10.11 R28.2(N2) R83.1
UART0A_RTS_32670: P8.7 P10.12 R38.2(N2) R85.1 R171.2(N2)
UART0A_RX_32670: P1.8 P8.8 P10.4 R26.2(N2) R89.1
UART0A_TX_32670: P1.6 P8.9 P10.3 R27.2(N2) R88.1
UART1A_CTS_32670: P10.14 R58.2(N2) R84.1
UART1A_RX_32670: P10.10 R56.2(N2) R87.1 R102.1
UART1A_TX_32670: P10.9(N9) R57.2(N2) R86.1 R103.1
UNNAMED_6_CN6P_I5_N1: P3.1 R68.1
UNNAMED_6_CN6P_I5_N2: P3.2 R69.1
UNNAMED_6_CN6P_I5_N3: P3.3 R74.1
UNNAMED_6_CN6P_I5_N4: P3.4 R165.1
UNNAMED_6_CN6P_I5_N5: P3.5 R77.1 R78.1
UNNAMED_6_CN6P_I5_N6: P3.6(N6) R76.1 R79.1
UNNAMED_6_CN6P_I101_N2: P5.2 R10.2(N2) R11.2(N2)
UNNAMED_6_CN8PA_I2_N3: P4.3 R75.1
UNNAMED_6_CN8PA_I2_N4: E1.1 P4.4
UNNAMED_6_CN8PA_I2_N5: E9.1 P4.5
UNNAMED_6_CN8PA_I2_N8: C39.1 E2.1 P4.8(N8)
UNNAMED_6_CN8PA_I132_N1: P7.1 R89.2(N2) R91.2(N2)
UNNAMED_6_CN8PA_I132_N2: P7.2 R88.2(N2) R90.2(N2)
UNNAMED_6_CN8PA_I132_N3: P7.3 R87.2(N2)
UNNAMED_6_CN8PA_I132_N4: P7.4 R86.2(N2)
UNNAMED_6_CN8PA_I132_N5: P7.5 R85.2(N2)
UNNAMED_6_CN8PA_I132_N6: P7.6 R84.2(N2)
UNNAMED_6_CN8PA_I132_N7: P7.7 R83.2(N2)
UNNAMED_6_CN8PA_I132_N8: P7.8(N8) R82.2(N2)
UNNAMED_6_CN8PODDEVEN_I6_N1: P9.1 R110.2(N2) R111.2(N2)
UNNAMED_6_CN8PODDEVEN_I6_N2: P9.2 R114.1 R115.1
UNNAMED_6_CN8PODDEVEN_I6_N3: P9.3 R112.2(N2) R113.2(N2)
UNNAMED_6_CN8PODDEVEN_I6_N4: P9.4 R116.1 R117.1
UNNAMED_6_CN8PODDEVEN_I6_N7: C41.1 E3.1 P9.7 P9.8(N8)
UNNAMED_6_CN10P_I39_N1: P1.1 R175.2(N2)
UNNAMED_6_CN10P_I131_N1: P6.1 R93.2(N2)
UNNAMED_6_CN10P_I131_N2: P6.2 R92.2(N2)
UNNAMED_6_CN12PV3_I7_P1: P8.1 R96.2(N2) R97.2(N2)
UNNAMED_6_CN12PV3_I7_VCC1: C40.1 E4.1 P8.6 P8.12(VCC2)
UNNAMED_6_CN18P_I78_N1: P2.1 R130.2(N2) R131.2(N2) R132.2(N2)
UNNAMED_6_CN18P_I79_N18: P10.18 R98.1 R144.1
UNNAMED_6_FERRITE_I116_N2: E2.2(N2) R12.1 R13.1 R127.1 R138.1 R166.1
UNNAMED_6_FERRITE_I117_N2: E1.2(N2) R143.1 R177.1
UNNAMED_6_FERRITE_I118_N2: E3.2(N2) R72.1 R73.1 R134.1 R167.1
UNNAMED_6_FERRITE_I121_N2: E4.2(N2) R70.1 R71.1 R133.1 R168.1
UNNAMED_6_FERRITE_I126_N2: E9.2(N2) R162.1 R163.1 R164.1
UNNAMED_6_RES_I73_N1: P4.2 R80.1 R81.1
UNNAMED_6_RES_I76_N1: P2.18 R94.1 R95.1
UNNAMED_6_RES_I103_N2: R14.1 R15.1 R128.2(N2) R129.2(N2)
UNNAMED_8_CAP_I10_N1: C22.1 C23.1 R101.1 U3.40
UNNAMED_8_CAP_I11_N2: C20.2(N2) C21.2(N2) E5.2(N2) U3.37
UNNAMED_8_CAP_I44_N1: C25.1 R158.2(N2) Y2.1
UNNAMED_8_CAP_I54_N1: C19.1 U3.32
UNNAMED_8_CAP_I89_N1: C42.1 E5.1 R99.2(N2) R100.2(N2)
UNNAMED_8_DIOLED_I64_P: DS1.A(P) R108.2(N2)
UNNAMED_8_DIOLED_I75_P: DS2.A(P) R109.2(N2)
UNNAMED_8_ICMAX3267X_I1_P0: R24.1 U3.10
UNNAMED_8_ICMAX3267X_I1_P0_1: R20.1 U3.6
UNNAMED_8_ICMAX3267X_I1_P0_2: R19.1 U3.5
UNNAMED_8_ICMAX3267X_I1_P0_3: R18.1 U3.4
UNNAMED_8_ICMAX3267X_I1_P0_4: R23.1 U3.9
UNNAMED_8_ICMAX3267X_I1_P0_5: R22.1 U3.8
UNNAMED_8_ICMAX3267X_I1_P0_6: R21.1 U3.7
UNNAMED_8_ICMAX3267X_I1_P0_7: R43.1 U3.27
UNNAMED_8_ICMAX3267X_I1_P0_8: R40.1 U3.24
UNNAMED_8_ICMAX3267X_I1_P0_9: R38.1 U3.23
UNNAMED_8_ICMAX3267X_I1_P0_10: R28.1 U3.22
UNNAMED_8_ICMAX3267X_I1_P0_11: R25.1 U3.11
UNNAMED_8_ICMAX3267X_I1_P0_12: R26.1 U3.20
UNNAMED_8_ICMAX3267X_I1_P0_13: R42.1 U3.26
UNNAMED_8_ICMAX3267X_I1_P0_14: R27.1 U3.21
UNNAMED_8_ICMAX3267X_I1_P0_15: R41.1 U3.25
UNNAMED_8_ICMAX3267X_I1_P0_16: R57.1 U3.18
UNNAMED_8_ICMAX3267X_I1_P0_17: R52.1 U3.13
UNNAMED_8_ICMAX3267X_I1_P0_18: R47.1 U3.31
UNNAMED_8_ICMAX3267X_I1_P0_19: R48.1 U3.1
UNNAMED_8_ICMAX3267X_I1_P0_20: R49.1 U3.2
UNNAMED_8_ICMAX3267X_I1_P0_21: R50.1 U3.3
UNNAMED_8_ICMAX3267X_I1_P0_22: R51.1 U3.12
UNNAMED_8_ICMAX3267X_I1_P0_23: R54.1 U3.15
UNNAMED_8_ICMAX3267X_I1_P0_24: R56.1 U3.17
UNNAMED_8_ICMAX3267X_I1_P0_25: R55.1 U3.16
UNNAMED_8_ICMAX3267X_I1_P0_26: R53.1 U3.14
UNNAMED_8_ICMAX3267X_I1_P0_27: R58.1 U3.19
UNNAMED_8_ICMAX3267X_I1_P0_28: R46.1 U3.30
UNNAMED_8_ICMAX3267X_I1_P0_29: R45.1 U3.29
UNNAMED_8_ICMAX3267X_I1_P0_30: R44.1 U3.28
UNNAMED_8_RES_I3_N2: R16.2(N2) R17.1 S1.1
UNNAMED_8_RES_I65_N1: Q1.3 R108.1
UNNAMED_8_RES_I66_N2: Q1.1 R102.2(N2) R104.2(N2) R105.1
UNNAMED_8_RES_I70_N2: Q2.1 R103.2(N2) R106.2(N2) R107.1
UNNAMED_8_RES_I72_N1: Q2.3 R109.1
UNNAMED_8_RES_I78_N1: R1.1 R3.1 R6.2(N2) R7.2(N2) R8.1 R9.1 R118.1 R119.1
UNNAMED_9_CAP_I41_N1: C67.1 J4.1 L22.2(N2)
UNNAMED_9_CAP_I56_N2: C58.2(N2) E6.2(N2) R66.1 U4.10
UNNAMED_9_CAP_I57_N1: C59.1 R66.2(N2) R67.2(N2) U4.11
UNNAMED_9_CAP_I93_N1: C62.1 R39.2(N2) U5.6
UNNAMED_9_CAP_I97_N1: C60.1 C61.1 L19.1 U4.24
UNNAMED_9_CAP_I100_N2: C28.2(N2) E7.2(N2) U5.4(VDD)
UNNAMED_9_CAP_I108_N1: C63.1 C65.1 L22.1
UNNAMED_9_CAP_I108_N2: C63.2(N2) R156.1 U5.5
UNNAMED_9_CAP_I126_N1: C66.1 FL2.1 L21.2(N2)
UNNAMED_9_CAP_I130_N2: C43.2(N2) E6.1 R145.2(N2) R146.2(N2)
UNNAMED_9_FERRITE_I118_N1: C44.1 E7.1 R147.2(N2) R148.2(N2)
UNNAMED_9_FLTRBP10P_I89_SWRFI: FL1.6 U5.3
UNNAMED_9_FLTRBP10P_I89_SWRFO: FL1.8(SW_RFO) U5.1
UNNAMED_9_ICSX126X_I1_BUSY: R36.1 U4.14
UNNAMED_9_ICSX126X_I1_DIO1: R29.2(N2) U4.13
UNNAMED_9_ICSX126X_I1_DIO3: R31.2(N2) U4.6
UNNAMED_9_ICSX126X_I1_MISO: R37.1 U4.16
UNNAMED_9_ICSX126X_I1_MOSI: R33.2(N2) U4.17
UNNAMED_9_ICSX126X_I1_NRESET: R32.2(N2) U4.15
UNNAMED_9_ICSX126X_I1_NSS: R35.2(N2) R65.2(N2) U4.19
UNNAMED_9_ICSX126X_I1_SCK: R34.2(N2) U4.18
UNNAMED_9_IND_I127_N2: L20.2(N2) L21.1 R156.2(N2)
UNNAMED_9_RES_I105_N2: R39.1 R135.2(N2) R136.2(N2)
UNNAMED_10_ADLTC3130V2_I172_BST1: C38.1 U2.1
UNNAMED_10_ADLTC3130V2_I172_BST2: C34.1 U2.16
UNNAMED_10_ADLTC3130V2_I172_PVIN: C30.2(N2) C31.2(N2) C32.2(N2) R153.1 R173.2(N2) R174.2(N2) U2.2 U2.3
UNNAMED_10_ADLTC3130V2_I172_SW1: C38.2(N2) L2.2(N2) U2.20
UNNAMED_10_ADLTC3130V2_I172_SW2: C34.2(N2) L2.1 U2.15
UNNAMED_10_ADMAX31334_I82_DIN: R4.2(N2) U7.B4
UNNAMED_10_ADMAX31334_I82_INTAN: R61.2(N2) R172.1 U7.A4
UNNAMED_10_ADMAX31334_I82_SCL: R2.2(N2) R59.2(N2) R60.2(N2) U7.C4
UNNAMED_10_ADMAX31334_I82_SDA: R5.2(N2) R63.1 R64.1 U7.C3
UNNAMED_10_ADMAX31334_I82_VBAT: C14.P U7.A1
UNNAMED_10_ADMAX31334_I82_VCC: C12.1 C13.1 E8.2(N2) U7.C1
UNNAMED_10_ADMAX31334_I82_X1: U7.A3 Y1.2(N2)
UNNAMED_10_ADMAX31334_I82_X2: U7.A2(X2) Y1.1
UNNAMED_10_ADMAX77675_I110_BST: C1.2(N2) U1.B3
UNNAMED_10_ADMAX77675_I110_IN: C29.2(N2) R169.2(N2) R170.2(N2) U1.D1
UNNAMED_10_ADMAX77675_I110_LXA: L1.2(N2) U1.D2
UNNAMED_10_ADMAX77675_I110_LXB: C1.1 L1.1 U1.C3
UNNAMED_10_ADMAX77675_I110_NIRQ: R120.1 R171.1 U1.B2
UNNAMED_10_ADMAX77675_I110_PVDD: C2.2(N2) C3.2(N2) C6.1 C7.1 U1.A2(VDD) U1.D4
UNNAMED_10_ADMAX77675_I110_SBB0: R139.1 U1.A3
UNNAMED_10_ADMAX77675_I110_SBB1: R140.1 U1.A4
UNNAMED_10_ADMAX77675_I110_SBB2: R141.1 U1.B4
UNNAMED_10_ADMAX77675_I110_SBB3: R142.1 U1.C4
UNNAMED_10_ADMAX77675_I110_SCL: R122.2(N2) R125.1 R126.1 U1.B1
UNNAMED_10_ADMAX77675_I110_SDA: R121.2(N2) R123.1 R124.1 U1.C1
UNNAMED_10_CN2P_I63_N2: D1.A(P) P11.2(N2)
UNNAMED_10_DIOLED_I195_P: DS3.A(P) R151.2(N2)
UNNAMED_10_DIOLED_I198_P: DS4.A(P) R152.2(N2)
UNNAMED_10_DIOLED_I201_P: DS5.A(P) R154.2(N2)
UNNAMED_10_DIOSCHOTTKY_I62_N: D1.C JP1.3
UNNAMED_10_NC3PJMPR_I56_A: BT1.1 JP1.1 TP2.1(N1)
UNNAMED_10_RES_I124_N1: R121.1 R122.1 R149.2(N2) R150.2(N2)
UNNAMED_10_RES_I143_N2: R137.2(N2) R176.1 U1.C2
VOUT_3130: C35.1 C36.1 C37.1 R133.2(N2) R134.2(N2) R143.2(N2) R144.2(N2) R145.1 R147.1 R154.1 R155.2(N2) R164.2(N2) U2.14
VREG_1261: C56.1 L17.1 L18.1 U4.7
VS1: JP2.2(COM) U2.10
VS2: JP3.2(COM) U2.9(VS2/FB)
XTA_1261: U4.3 Y4.1
XTB_1261: U4.4(XTB) Y4.3(N2)

Pads without a net: FL2 2; P1 7 9; P2 14 15 16; P4 1; P6 8; P10 15 16 17; U7 B2

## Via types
v1: diameter 0.508, hole 0.254, TOP to BOTTOM, 785 vias
v2: diameter 0.254, hole 0.127, TOP to BOTTOM, 12 vias

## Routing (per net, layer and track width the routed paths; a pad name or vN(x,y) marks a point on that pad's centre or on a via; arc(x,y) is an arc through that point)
0V7_SSB2: length 32.9
  L3_PWR w0.508: v1(46.23,9.47) 45.59,8.84 41.5,8.84 40.51,7.85 36.83,7.85 36.47,8.2 v1(36.47,8.46)
  L3_PWR w0.762: v1(46.23,9.47) 46.23,9.98 46.79,10.54 53.59,10.54 54.97,9.17 57.23,9.17 58.46,10.4 TP6.1 58.46,11.52 61.25,14.31
  BOTTOM w0.508: R177.2 35.76,8.86 36.17,8.46 v1(36.47,8.46) ; v1(46.23,9.47) 46.08,9.63 R127.2
  vias: v1(61.14,15.73) v1(61.14,15.02) v1(61.85,15.73) v1(61.85,15.02)
1V1_SSB1: length 28.2
  BOTTOM w0.508: TP5.1 63.18,12.84 v1(61.96,12.84) v1(61.25,12.84) 60.54,12.84 58.81,14.57 57.06,14.57 56.82,14.33 49.22,14.33 R101.2 48.15,12.51 47.9,12.27 41.61,12.27 40.29,13.58 R163.2
1V8_SSB0: length 206.1
  TOP w0.203: C9.1 65.9,12.04 v1(65.9,12.61)
  TOP w0.508: v1(82.54,40.73) 81.65,41.61 81.65,42.68 82.21,43.24 v1(82.21,45.9) ; R67.1 33.07,22.05 35.51,19.61 37.69,19.61 38.71,18.59 v1(38.71,16.61) 38.71,12.14 39.55,11.3 43.48,11.3 v1(44.02,10.77)
  TOP w0.762: v1(83.24,22.44) 83.59,22.09 83.59,14.91 81,12.32 78.92,12.32 76.81,10.21 v1(76.81,8.51)
  TOP w1.016: v1(83.24,22.44) v1(82.53,22.44) 81.86,22.44 81.43,22.86 81.43,24.77 79.48,26.72 79.48,29.74 83.35,33.62 83.35,40.62 v1(83.25,40.73) v1(82.54,40.73)
  L3_PWR w0.508: 63.3,17.35 61.37,17.35 60.3,16.28 60.3,14.63 57.39,11.72 57.39,10.53 56.87,10.01 55.35,10.01 53.98,11.38 51.25,11.38 v1(50.12,12.51) 49.04,11.43 44.68,11.43 v1(44.02,10.77) 42.95,9.7 41.83,9.7 40.82,10.72 36.25,10.72 33.77,8.24 33.77,5.01 33.27,4.52 21.89,4.52 20.24,2.87 18.33,2.87 v1(18.05,2.58)
  L3_PWR w1.016: v1(65.9,12.61) 63.3,15.21 63.3,23.15 65.12,24.97 v1(67.08,24.97) 69.71,27.6 78.32,27.6 81.37,24.55 81.37,23.08 82.01,22.44 v1(82.53,22.44) v1(83.24,22.44)
  BOTTOM w0.508: v1(50.12,12.51) 50.27,12.35 R6.1 ; R131.1 v1(18.05,2.58) 18.77,2.58 R80.2 ; R13.2 43.83,10.58 v1(44.02,10.77) ; R16.1 74.38,51.63 79.95,51.63 81.39,50.18 81.39,46.24 81.74,45.9 v1(82.21,45.9) ; v1(67.08,24.97) 69.09,24.97 71.04,23.01 R149.1 ; v1(76.81,8.51) 78.92,8.51 81.17,6.26 81.17,3.52 82.07,2.62 85.57,2.62 85.82,2.87 R128.1 ; v1(38.71,16.61) 38.82,16.5 R99.1
  BOTTOM w0.635: R71.2 v1(82.54,40.73) v1(83.25,40.73) ; R73.2 v1(82.53,22.44) v1(83.24,22.44)
  vias: v1(66.61,12.61) v1(67.25,12.28) v1(67.32,11.49)
3V3_SSB3: length 233.1
  TOP w0.508: v1(77.83,7.76) 77.83,10.01 79.15,11.33 v1(81.61,11.33) ; v1(42.34,10.58) 39.23,10.58 38,11.81 v1(38,14.72) 38,18.29 37.44,18.85 35.2,18.85 32.92,21.13 v1(31.95,21.13) ; v1(55.79,10.73) 55.79,9.51 55.43,9.15 R94.2 ; R98.2 56.2,32.62 v1(56.52,32.31)
  TOP w0.762: 83.72,23.7 84.3,23.7 84.84,23.16 84.84,14.55 v1(81.61,11.33)
  TOP w1.016: 83.82,42.04 84.57,41.29 84.57,33.11 80.8,29.34 80.8,27.23 82.73,25.3 82.73,24.66
  L3_PWR w0.508: v1(56.52,32.31) 57.02,31.8 61.72,31.8 63.6,29.92 63.98,29.92 ; v1(13.07,2.58) 14.08,3.59 v1(18.04,3.59) 19.74,3.59 21.07,4.91 21.07,6.33 21.72,6.99 31.42,6.99 36.17,11.73 41.19,11.73 v1(42.34,10.58) 43.92,12.17 48.64,12.17 49.79,13.32 v1(50.12,13.32) 50.46,13.32 51.69,12.09 54.43,12.09 v1(55.79,10.73) 55.79,11.52 56.39,12.12 56.39,13.69 57.3,14.61 58.72,14.61 59.49,15.37 59.49,16.85 v1(61.12,18.47)
  L3_PWR w1.27: 82.87,24.12 82.87,25.08 78.96,28.99 72.4,28.99 70.92,30.48 v1(65.29,30.48) 64.54,30.48 63.98,29.92 63.98,25.86 60.63,22.51 60.63,19.72 61.62,18.73
  BOTTOM w0.381: R120.2 67.08,17.5 67.46,17.88 67.46,19.66 67.89,20.09 68.68,20.09 69.26,20.67 R150.1
  BOTTOM w0.508: R100.1 v1(38,14.72) ; R7.1 50.22,13.42 v1(50.12,13.32) ; R148.1 23.93,22.74 R146.1 27.45,22.74 27.76,22.43 27.76,20.98 28.37,20.37 31.19,20.37 v1(31.95,21.13) ; Q1.2 76.26,1.78 76.28,1.76 ; 71.51,1.76 R104.1 76.28,1.76 ; 71.51,1.76 70.1,1.76 R106.1 ; 71.51,1.76 71.51,1.77 Q2.2 ; R175.1 R129.1 85.83,7.11 v1(81.61,11.33) ; R12.2 v1(42.34,10.58) ; v1(77.83,7.76) 77.83,6.55 79.03,5.35 79.03,1.99 78.8,1.76 76.28,1.76 ; R130.1 v1(13.07,2.58) ; R81.2 v1(18.04,3.59) ; R150.1 70.15,20.85 70.15,22.89 68.78,24.26 64.43,24.26 62.54,22.36 61.45,22.36 60.71,21.62 TP7.1 61.12,20.01 v1(61.12,19.19) ; R10.1 v1(65.29,30.48)
  BOTTOM w0.635: R72.2 v1(82.53,23.58) v1(83.24,23.58) ; R70.2 v1(82.54,41.87) v1(83.25,41.87)
  vias: v1(61.83,19.19) v1(61.83,18.47)
GND: length 316.3
  TOP w0.152: Y4.4 Y4.2
  TOP w0.203: 39.27,15.22 C26.2 ; 39.27,15.22 39.27,16.51 39.6,16.84 42.08,16.84 42.12,16.8 v1(43.81,16.8) ; 39.27,15.22 39.27,13.68 ; 19.33,15.88 19.38,15.88 C61.2 v1(19.38,14.79) ; C4.N v1(6.77,43.42) ; C25.2 39.27,13.68 ; 39.27,13.68 39.27,12.4 39.6,12.07 42.85,12.07 43.21,12.42 43.21,13.26 43.84,13.89 44.45,13.89 44.63,14.07 44.63,15.52 44.98,15.88 v1(45.34,15.88) ; v1(42.04,24.38) 42.27,24.16 43.18,24.16 44.33,23.01 v1(44.33,21.88) ; Y3.4 38.31,21.62 38.18,21.75 38.18,25.59 38.43,25.83 v1(38.46,25.83) 38.48,25.86 40.59,25.86 40.81,25.64 Y3.2
  TOP w0.229: C21.1 44.19,18.53 U3.36
  TOP w0.254: U2.18 v1(30.23,40.54) ; U1.A1 68.76,15.95 69.38,15.32 C3.1 ; U1.D3 65.06,18.01 v1(64.34,18.73) ; C12.2 47.75,43.24 U7.B1 ; v1(20.6,22.03) FL1.5 v2(20.6,20.51) ; v1(26.59,38.46) 26.76,38.62 U2.12 ; v2(20.6,20.01) FL1.2 v2(21.82,20.01) ; v2(20.6,20.01) 20.6,19.52 ; v2(20.6,20.01) v2(20.6,20.51) ; 20.6,19.52 20.6,19.51 FL1.9 19.43,19.51 v1(19.18,19.26) ; 20.6,19.52 FL1.10 v1(20.6,18.47) ; v2(20.6,20.51) 20.6,20.51 FL1.7 v2(19.33,20.51) U5.2
  TOP w0.279: U2.8 25.61,41.04 24.72,41.04 ; U2.7 24.96,41.54
  TOP w0.305: v1(24.63,14.11) Y4.4 v1(23.68,13.21) ; 26.48,20.01 U4.5 26.48,18.31 v1(26.98,17.81) v1(27.74,17.81) ; 26.48,20.01 U4.8 28.39,20.01 28.86,19.54 v1(29.01,19.54) ; 26.48,20.01 v1(26.07,20.42) U4.PAD ; v1(26.08,11.16) Y4.2 v1(27.03,12.06) ; U4.PAD v1(25.4,20.42) 24.98,20.01 U4.2 24.98,18.31 v1(24.49,17.81) ; U4.PAD v1(25.4,21.1) 24.98,21.51 U4.20 22.95,21.51 22.68,21.78 v1(22.68,21.82) ; v1(30.81,21.13) 30.74,21.2 C58.1
  TOP w0.508: 39.23,2.54 P4.7 36.97,2.54 ; P11.1 3.84,37.44 ; P11.1 2.64,36.25 ; P11.1 5.03,36.25 ; P11.1 3.84,35.05 ; v1(86.77,6.89) P1.5 83.4,6.89 83.39,6.88 ; DS3.C v1(73.15,50.22) ; 75.19,37.08 P8.5 ; P8.5 77.33,37.08 ; P8.5 76.26,36.02 ; P8.5 76.26,38.15 ; DS2.C 72.57,2.78 ; DS2.C DS1.C 79.4,1.88 v1(79.73,1.55) ; DS2.C 71.67,1.88 ; P8.11 78.8,38.15 ; P8.11 78.8,36.02 ; P8.11 77.73,37.08 ; C39.2 41.01,8.97 v1(39.98,8.97) ; 51.15,37.91 R62.2 ; R62.2 51.77,38.58 ; R62.2 51.15,39.26 ; v1(44.68,23.57) 45.19,23.06 C19.2 ; 77.72,18.8 P9.6 ; P9.6 78.79,17.73 ; P9.6 78.79,19.86 ; P9.6 79.86,18.8 ; 22.47,50.8 P6.7 20.21,50.8 ; C59.2 31.98,24.13 v1(32.11,24) ; 83.52,5.61 83.52,5.62 P1.3 v1(86.77,5.62) ; v1(43.74,19.44) 44.05,19.14 C21.1 ; v1(45.39,13.26) 45.27,13.37 C22.2 C23.2 ; Y3.4 39.11,20.89 v1(39.7,20.29) 42,20.29 C27.2 v1(43.18,20.62) ; 75.18,18.8 P9.5 ; P9.5 76.25,19.86 ; P9.5 76.25,17.73 ; P9.5 77.32,18.8 ; DS5.C v1(82.42,50.16) ; C26.2 40.64,14.64 v1(40.64,14.45) ; C7.2 v1(64.34,19.62) ; 20.09,33.86 JP4.1 ; JP4.1 19.02,34.47 ; JP4.1 21.16,34.47 ; Y3.2 41.1,24.38 v1(42.04,24.38) ; TP1.1 12.17,28.5 ; TP1.1 11.48,29.19 ; TP1.1 11.48,27.81 ; TP1.1 10.79,28.5 ; DS4.C 77.8,50.39 77.56,50.15 v1(77.2,50.15) ; v1(51.94,35.79) 51.54,35.38 R4.1 ; C24.2 v1(43.18,22.52) ; C32.1 v1(27.25,46.25) ; C20.1 v1(43.03,19.44) ; R176.2 v1(65.11,23.52)
  TOP w0.61: JP3.1 v1(20.09,40.89) ; JP2.1 v1(20.09,37.21)
  L2_GND w0.508: 54.28,39.65 BT1.2 ; BT1.2 54.28,42.29 ; BT1.2 52.96,40.97 ; BT1.2 55.6,40.97 ; 76.25,17.73 P9.5 ; P9.5 76.25,19.86 ; P9.5 75.18,18.8 ; P9.5 77.32,18.8 ; 34.43,2.54 P4.6 ; P4.6 36.69,2.54 ; P4.6 35.56,3.67 ; 76.26,36.02 P8.5 ; P8.5 76.26,38.15 ; P8.5 75.19,37.08 ; P8.5 77.33,37.08 ; 3.84,35.05 P11.1 ; P11.1 5.03,36.25 ; P11.1 2.64,36.25 ; P11.1 3.84,37.44 ; P4.7 38.1,3.67 ; P4.7 36.97,2.54 ; P4.7 39.23,2.54 ; 77.73,37.08 P8.11 ; P8.11 78.8,36.02 ; P8.11 79.87,37.08 ; P8.11 78.8,38.15 ; C14.N 68.49,46.81 ; C14.N 68.49,44.04 ; C14.N 69.87,45.43 ; C14.N 67.1,45.43 ; TP1.1 11.48,29.19 ; TP1.1 11.48,27.81 ; TP1.1 12.17,28.5 ; TP1.1 10.79,28.5 ; P9.6 79.86,18.8 ; P9.6 77.72,18.8 ; P9.6 78.79,17.73 ; P9.6 78.79,19.86 ; 61.09,24.27 P5.6 ; P5.6 62.22,25.4 ; P5.6 61.09,26.53 ; P5.6 59.96,25.4 ; 21.34,49.67 P6.7 ; P6.7 20.21,50.8 ; P6.7 22.47,50.8 ; 52.82,4.69 P2.17 ; P2.17 52.82,6.82 ; P2.17 53.88,5.75 ; P2.17 51.75,5.75
  L3_PWR w0.508: 52.96,40.97 BT1.2 ; BT1.2 55.6,40.97 ; BT1.2 54.28,39.65 ; BT1.2 54.28,42.29 ; P9.5 76.25,19.86 ; P9.5 75.18,18.8 ; P9.5 77.32,18.8 ; P9.5 76.25,17.73 ; 10.79,28.5 TP1.1 ; TP1.1 12.17,28.5 ; TP1.1 11.48,29.19 ; TP1.1 11.48,27.81 ; 67.1,45.43 C14.N ; C14.N 68.49,46.81 ; C14.N 69.87,45.43 ; C14.N 68.49,44.04 ; 3.84,35.05 P11.1 ; P11.1 5.03,36.25 ; P11.1 2.64,36.25 ; P11.1 3.84,37.44 ; P2.17 53.88,5.75 ; P2.17 52.82,4.69 ; P2.17 52.82,6.82 ; P2.17 51.75,5.75 ; P4.7 38.1,3.67 ; P4.7 39.23,2.54 ; P4.7 36.97,2.54 ; 78.8,36.02 P8.11 ; P8.11 77.73,37.08 ; P8.11 78.8,38.15 ; P8.11 79.87,37.08 ; P8.5 76.26,38.15 ; P8.5 77.33,37.08 ; P8.5 75.19,37.08 ; P8.5 76.26,36.02 ; 61.09,26.53 P5.6 59.96,25.4 ; 34.43,2.54 P4.6 ; P4.6 36.69,2.54 ; P4.6 35.56,3.67 ; 77.72,18.8 P9.6 ; P9.6 78.79,17.73 ; P9.6 78.79,19.86 ; P9.6 79.86,18.8 ; 21.34,49.67 P6.7 ; P6.7 22.47,50.8 ; P6.7 20.21,50.8
  BOTTOM w0.508: P6.7 22.47,50.8 ; P6.7 20.21,50.8 ; P6.7 21.34,49.67 ; 36.97,2.54 P4.7 39.23,2.54 ; P8.5 77.33,37.08 ; P8.5 75.19,37.08 ; P8.5 76.26,36.02 ; 78.79,17.73 P9.6 ; P9.6 78.79,19.86 ; P9.6 77.72,18.8 ; 19.35,17.83 C62.2 ; C62.2 19.94,18.47 ; C62.2 19.35,19.1 ; C14.N 69.87,45.43 ; C14.N 67.1,45.43 ; C14.N 68.49,44.04 ; C14.N 68.49,46.81 ; C43.1 29.16,21.86 29.88,21.13 v1(30.81,21.13) ; 11.48,27.81 TP1.1 ; TP1.1 12.17,28.5 ; TP1.1 10.79,28.5 ; TP1.1 11.48,29.19 ; 78.8,36.02 P8.11 ; P8.11 77.73,37.08 ; P8.11 78.8,38.15 ; C42.2 42.05,18.63 ; C42.2 43.09,17.53 v1(43.81,16.8) ; C42.2 42.05,16.42 ; 34.43,2.54 P4.6 36.69,2.54 ; R17.2 72.95,50.59 ; R17.2 71.6,50.59 ; R17.2 72.28,49.97 ; 17.75,24 C28.1 18.39,24.59 ; 21.87,21.97 C44.2 20.76,22.92 ; P9.5 77.32,18.8 ; P9.5 76.25,17.73 ; P9.5 75.18,18.8 ; P11.1 3.84,37.44 ; P11.1 5.03,36.25 ; P11.1 3.84,35.05 ; P11.1 2.64,36.25 ; BT1.2 55.6,40.97 ; BT1.2 52.96,40.97 ; BT1.2 54.28,42.29 ; R105.2 v1(75.72,4.72) ; v1(72.83,6.77) 73.11,7.04 R107.2
  BOTTOM w0.635: v1(82.38,36.66) v1(82.38,35.95) 82.67,35.67 C40.2 ; C41.2 82.66,17.53 v1(82.52,17.68) v1(82.52,18.39)
  vias: v1(1.58,50.26) v1(1.58,47.72) v1(1.58,45.18) v1(1.58,42.64) v1(1.58,40.1) v1(1.58,37.56) v1(1.58,35.02) v1(1.58,32.48) v1(1.58,18.97) v1(1.58,16.57) v1(1.58,14.51) v1(1.58,12.53) v1(1.58,10.47) v1(1.58,8.07) v1(1.6,4.67) v1(1.6,1.88) v1(1.68,11.56) v1(1.85,15.54) v1(2.34,12.52) v1(2.36,18.97) v1(2.41,8.05) v1(2.59,10.52) v1(2.64,32.82) v1(2.79,14.78) v1(2.9,16.54) v1(3.18,38.96) v1(3.2,15.6) v1(3.18,11.63) v1(3.61,16.51) v1(3.61,12.5) v1(3.73,14.53) v1(3.76,32.49) v1(3.78,18.97) v1(3.81,8.03) v1(3.94,10.46) v1(4.29,11.91) v1(4.39,32.92) v1(4.5,15.44) v1(4.67,18.97) v1(4.7,8) v1(4.78,14.61) v1(4.75,1.85) v1(4.88,16.56) v1(5.03,5.31) v1(5.05,50.8) v1(5.05,48.26) v1(5.05,45.72) v1(5.13,10.59) v1(5.18,32.46) v1(5.38,38.96) v1(5.36,12.7) v1(5.54,15.93) v1(5.64,18.59) v1(5.64,17.4) v1(5.56,11.53) v1(5.82,9.58) v1(6.01,44.18) v1(6.01,43.42) v1(5.99,14.38) v1(5.99,12.27) v1(6.02,8.46) v1(6.17,32.82) v1(6.25,34.49) v1(6.25,7.42) v1(6.35,10.36) v1(6.6,18.92) v1(6.55,16.69) v1(6.71,12.7) v1(6.73,11.33) v1(6.68,6.5) v1(6.77,44.18) v1(6.83,15.04) v1(7.04,36.68) v1(7.04,32.46) v1(7.04,8.08) v1(7.19,18.03) v1(7.28,45.48) v1(7.26,9.4) v1(7.42,12.01) v1(7.49,18.95) v1(7.49,15.98) v1(7.52,14.45) v1(7.57,10.52) v1(7.67,32.79) v1(7.8,6.45) v1(7.87,36.65) v1(8.04,45.48) v1(7.98,17.17) v1(8.08,8.59) v1(8.2,11.48) v1(8.26,12.7) v1(8.34,38.87) v1(8.43,35.59) v1(8.36,15.27) v1(8.51,7.14) v1(8.56,18.9) v1(8.61,9.7) v1(8.69,32.46) v1(8.74,17.98) v1(8.92,14.35) v1(8.92,12.27) v1(8.89,10.74) v1(8.99,34.52) v1(9.07,16.56) v1(9.14,6.45) v1(9.4,15.72) v1(9.53,18.95) v1(9.5,9.04) v1(9.6,12.7) v1(9.55,8) v1(9.83,14.5) v1(9.86,32.66) v1(9.91,18.26) v1(10.01,11.35) v1(10.06,10.24) v1(10.21,29.75) v1(10.21,24.67) v1(10.24,23.77) v1(10.19,21.69) v1(10.19,20.27) v1(10.21,19.52) v1(10.34,29.03) v1(10.26,27.99) v1(10.31,26.47) v1(10.41,12.37) v1(10.52,16.56) v1(10.49,15.47) v1(10.47,8.07) v1(10.54,27.23) v1(10.67,25.5) v1(10.79,20.85) v1(10.82,13.26) v1(10.9,23.27) v1(10.9,8.89) v1(10.97,21.67) v1(11,18.82) v1(11,17.65) v1(11.1,11.5) v1(11.1,10.24) v1(11.05,7.37) v1(11.35,20.02) v1(11.43,16.13) v1(11.48,25.94) v1(11.53,24.08) v1(11.61,13.67) v1(11.73,25.02) v1(11.74,12.7) v1(11.77,38.95) v1(11.81,27.05) v1(11.96,20.78) v1(11.96,17.09) v1(12.12,18.59) v1(12.14,21.67) v1(12.17,8.15) v1(12.32,23.27) v1(12.24,14.68) v1(12.27,9.98) v1(12.34,27.74) v1(12.4,19.81) v1(12.37,11.5) v1(12.52,26.24) v1(12.6,8.99) v1(12.67,24.82) v1(12.79,34.71) v1(12.75,32.72) v1(12.78,12.52) v1(12.93,23.67) v1(12.85,21.29) v1(12.85,13.72) v1(12.98,28.3) v1(13,17.58) v1(13.11,27.08) v1(13.06,15.21) v1(13.06,7.57) v1(13.23,19.35) v1(13.28,10.41) v1(13.39,20.45) v1(13.51,25.32) v1(13.54,21.67) v1(13.54,18.49) v1(13.49,15.9) v1(13.54,23.27) v1(13.64,11.5) v1(13.84,26.34) v1(13.87,12.61) v1(13.94,28.55) v1(13.94,24.46) v1(14.02,8.94) v1(14.06,45.22) v1(14.06,42.76) v1(14.07,27.51) v1(14.1,15.44) v1(14.1,14.17) v1(14.07,9.98) v1(14.15,7.9) v1(14.33,19.96) v1(14.4,19.02) v1(14.5,21.62) v1(14.45,20.88) v1(14.48,16.54) v1(14.55,23.22) v1(14.69,11.52) v1(14.71,1.55) v1(14.86,17.22) v1(15.04,23.95) v1(15.12,25.46) v1(15.06,12.98) v1(15.16,21.23) v1(15.29,19.89) v1(15.32,16.46) v1(15.49,23.19) v1(15.7,17.91) v1(15.72,11.84) v1(15.79,47.23) v1(15.82,20.52) v1(15.88,12.95) v1(16.03,15.72) v1(16.03,15.01) v1(16.03,13.82) v1(15.98,10.77) v1(16.06,26.5) v1(16.1,24.21) v1(16.06,9.2) v1(16.21,27.79) v1(16.23,18.64) v1(16.21,16.74) v1(16.33,22.3) v1(16.46,25.68) v1(16.54,23.22) v1(16.71,17.81) v1(16.84,27.05) v1(16.98,45.25) v1(17.01,42.74) v1(16.98,38.52) v1(16.98,36.66) v1(17.02,19) v1(17.09,21.84) v1(17.33,25.23) v1(17.3,24.49) v1(17.25,17.09) v1(17.25,1.55) v1(17.42,26.11) v1(17.42,16.26) v1(17.4,13.36) v1(17.42,11.46) v1(17.53,23.49) v1(17.45,9.63) v1(17.6,27.53) v1(17.58,22.56) v1(17.63,21.34) v1(17.58,19.74) v1(17.55,18.41) v1(17.7,12.4) v1(17.65,10.67) v1(18.29,26.62) v1(18.31,7.65) v1(18.35,29.25) v1(18.39,24.97) v1(18.36,8.74) v1(18.62,25.88) v1(18.81,45.99) v1(18.76,27.47) v1(18.86,47.18) v1(19.1,22.05) v1(19.08,7.82) v1(19.36,13.73) v1(19.36,12.84) v1(19.36,11.95) v1(19.36,11.06) v1(19.36,10.17) v1(19.76,21.74) v1(19.82,7.82) v1(19.79,1.55) v1(19.88,29.25) v1(19.99,9.51) v1(20.15,14.79) v1(20.15,13.67) v1(20.91,13.67) v1(20.88,9.51) v1(21.37,34.76) v1(21.39,21.74) v1(21.54,18.85) v1(21.79,41.94) v1(21.79,41.17) v1(21.77,9.51) v1(21.95,12.07) v1(22.66,9.51) v1(22.8,34.15) v1(23.19,7.92) v1(23.32,29.08) v1(23.6,38) v1(23.55,9.51) v1(23.71,45.2) v1(23.68,14.11) v1(23.77,28.45) v1(24.54,28.98) v1(24.59,41.94) v1(24.59,41.17) v1(24.72,21.78) v1(24.72,21.1) v1(24.72,20.42) v1(24.72,19.74) v1(25.41,34.51) v1(25.4,21.78) v1(25.4,19.74) v1(26.07,21.78) v1(26.07,21.1) v1(26.07,19.74) v1(26.44,41.35) v1(26.44,40.23) v1(26.75,21.78) v1(26.75,21.1) v1(26.75,20.42) v1(26.75,19.74) v1(27.03,11.16) v1(27.08,34.92) v1(27.08,34.19) v1(27.2,14.15) v1(27.51,41.35) v1(27.51,40.23) v1(28.57,41.35) v1(28.57,40.23) v1(29.39,12.29) v1(30.15,12.29) v1(30.91,12.29) v1(31.06,40.54) v1(32.63,44.06) v1(33.36,44.06) v1(33.62,44.84) v1(33.93,34.92) v1(33.93,34.21) v1(34.35,44.84) v1(34.47,27.33) v1(34.65,34.92) v1(34.67,34.21) v1(34.82,15.39) v1(34.82,14.66) v1(34.82,13.89) v1(34.85,22.89) v1(34.85,22.17) v1(34.85,21.46) v1(35.38,34.92) v1(36.42,28.7) v1(36.6,10.01) v1(36.6,9.27) v1(36.7,28.02) v1(38.61,51.79) v1(38.61,50.22) v1(39.29,43.97) v1(39.29,43.26) v1(42.44,1.55) v1(42.6,40.34) v1(42.82,34.77) v1(43.31,40.34) v1(43.92,1.55) v1(47.38,20.2) v1(47.38,19.47) v1(47.38,18.73) v1(47.38,17.99) v1(47.38,17.26) v1(48.11,20.2) v1(48.11,19.47) v1(48.11,18.73) v1(48.11,17.99) v1(48.11,17.26) v1(48.26,43.59) v1(48.77,44.15) v1(48.9,41.91) v1(48.9,40.03) v1(48.87,24.21) v1(48.85,20.2) v1(48.85,19.47) v1(48.85,18.73) v1(48.85,17.99) v1(48.85,17.26) v1(49.58,20.2) v1(49.58,19.47) v1(49.58,18.73) v1(49.58,17.99) v1(49.58,17.26) v1(50.32,20.2) v1(50.32,19.47) v1(50.32,18.73) v1(50.32,17.99) v1(50.32,17.26) v1(50.55,42.67) v1(51.77,40.94) v1(51.77,39.83) v1(53.76,46.37) v1(54.53,23.98) v1(57.14,13.35) v1(57.14,12.64) v1(57.3,22.56) v1(57.56,17.35) v1(57.59,15.68) v1(57.69,13.8) v1(58.05,16.24) v1(58.4,13.8) v1(58.59,19.04) v1(58.6,16.7) v1(60.95,50.13) v1(64.15,11.72) v1(64.34,20.41) v1(64.91,9.72) v1(64.91,9) v1(64.94,8.27) v1(65.62,8.9) v1(69.23,1.82) v1(69.65,35.76) v1(70.15,14.73) v1(70.82,37.97) v1(72.92,36.98) v1(73.89,34.14) v1(74.46,37.6) v1(74.87,17.36) v1(75.16,19.56) v1(75.26,26.61) v1(75.48,30.24) v1(76.03,13.98) v1(76.97,6.9) v1(78.68,6.9) v1(78.8,13.98) v1(79.9,3.26) v1(82.27,1.55) v1(83.06,8.15) v1(84.39,48.02) v1(84.43,10.82) v1(84.81,1.55) v1(84.95,29.58) v1(87.35,51.47) v1(87.35,48.93) v1(87.35,46.39) v1(87.35,43.85) v1(87.35,41.31) v1(87.35,38.77) v1(87.35,36.23) v1(87.35,33.69) v1(87.35,31.15) v1(87.35,28.61) v1(87.35,26.07) v1(87.35,23.53) v1(87.35,20.99) v1(87.35,18.45) v1(87.35,15.91) v1(87.35,13.37) v1(87.35,10.83) v1(87.35,8.29) v1(87.35,1.55)
